VERSION 5.8 ;
BUSBITCHARS "[]" ;
DIVIDERCHAR "/" ;
UNITS
    DATABASE MICRONS 1000 ;
END UNITS

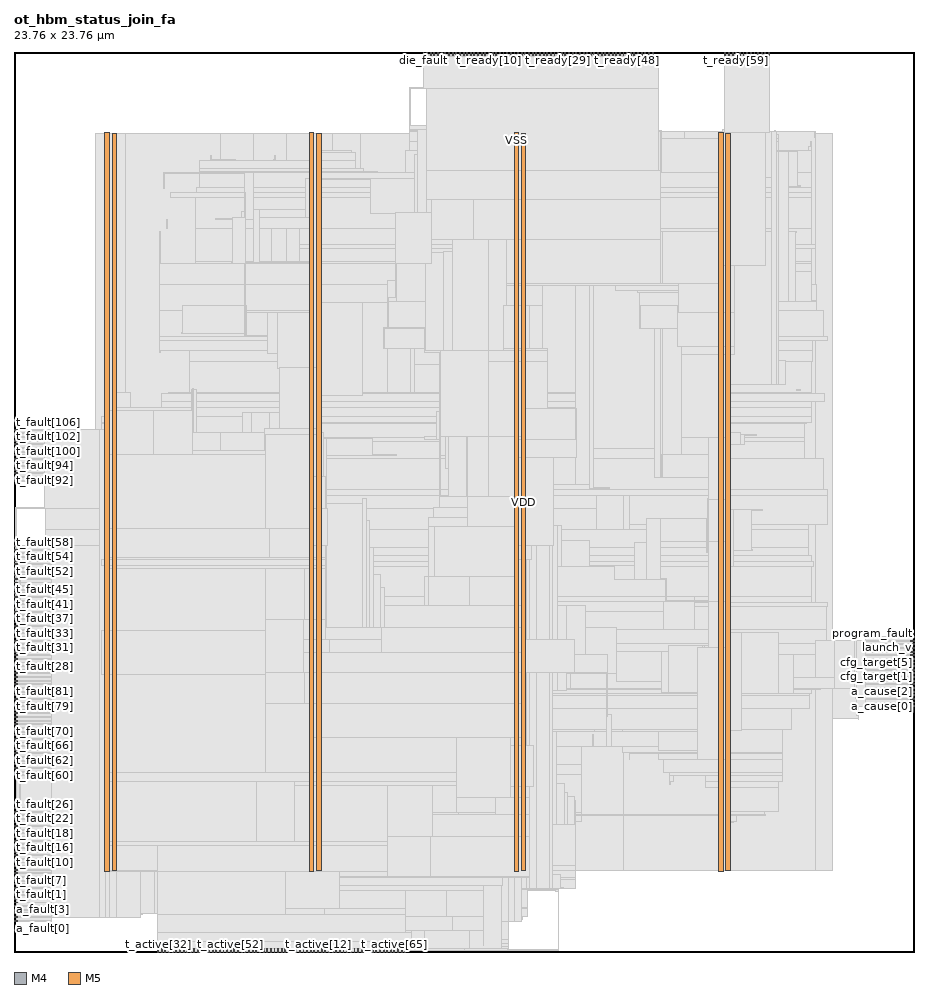
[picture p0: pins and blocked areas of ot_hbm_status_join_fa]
MACRO ot_hbm_status_join_fa
  FOREIGN ot_hbm_status_join_fa 0 0 ;
  CLASS BLOCK ;
  SIZE 23.76 BY 23.76 ;
  PIN a_cause[0]
    DIRECTION OUTPUT ;
    USE SIGNAL ;
    PORT
      LAYER M4 ;
        RECT  23.676 6.48 23.76 6.504 ;
    END
  END a_cause[0]
  PIN a_cause[1]
    DIRECTION OUTPUT ;
    USE SIGNAL ;
    PORT
      LAYER M4 ;
        RECT  23.676 6.576 23.76 6.6 ;
    END
  END a_cause[1]
  PIN a_cause[2]
    DIRECTION OUTPUT ;
    USE SIGNAL ;
    PORT
      LAYER M4 ;
        RECT  23.676 6.672 23.76 6.696 ;
    END
  END a_cause[2]
  PIN a_cause[3]
    DIRECTION OUTPUT ;
    USE SIGNAL ;
    PORT
      LAYER M4 ;
        RECT  23.676 6.768 23.76 6.792 ;
    END
  END a_cause[3]
  PIN a_fault[0]
    DIRECTION INPUT ;
    USE SIGNAL ;
    PORT
      LAYER M4 ;
        RECT  0 0.816 0.084 0.84 ;
    END
  END a_fault[0]
  PIN a_fault[1]
    DIRECTION INPUT ;
    USE SIGNAL ;
    PORT
      LAYER M4 ;
        RECT  0 0.912 0.084 0.936 ;
    END
  END a_fault[1]
  PIN a_fault[2]
    DIRECTION INPUT ;
    USE SIGNAL ;
    PORT
      LAYER M4 ;
        RECT  0 1.008 0.084 1.032 ;
    END
  END a_fault[2]
  PIN a_fault[3]
    DIRECTION INPUT ;
    USE SIGNAL ;
    PORT
      LAYER M4 ;
        RECT  0 1.104 0.084 1.128 ;
    END
  END a_fault[3]
  PIN block_ready
    DIRECTION OUTPUT ;
    USE SIGNAL ;
    PORT
      LAYER M4 ;
        RECT  23.676 6.864 23.76 6.888 ;
    END
  END block_ready
  PIN cfg_target[0]
    DIRECTION INPUT ;
    USE SIGNAL ;
    PORT
      LAYER M4 ;
        RECT  23.676 6.96 23.76 6.984 ;
    END
  END cfg_target[0]
  PIN cfg_target[1]
    DIRECTION INPUT ;
    USE SIGNAL ;
    PORT
      LAYER M4 ;
        RECT  23.676 7.056 23.76 7.08 ;
    END
  END cfg_target[1]
  PIN cfg_target[2]
    DIRECTION INPUT ;
    USE SIGNAL ;
    PORT
      LAYER M4 ;
        RECT  23.676 7.152 23.76 7.176 ;
    END
  END cfg_target[2]
  PIN cfg_target[3]
    DIRECTION INPUT ;
    USE SIGNAL ;
    PORT
      LAYER M4 ;
        RECT  23.676 7.248 23.76 7.272 ;
    END
  END cfg_target[3]
  PIN cfg_target[4]
    DIRECTION INPUT ;
    USE SIGNAL ;
    PORT
      LAYER M4 ;
        RECT  23.676 7.344 23.76 7.368 ;
    END
  END cfg_target[4]
  PIN cfg_target[5]
    DIRECTION INPUT ;
    USE SIGNAL ;
    PORT
      LAYER M4 ;
        RECT  23.676 7.44 23.76 7.464 ;
    END
  END cfg_target[5]
  PIN cfg_target[6]
    DIRECTION INPUT ;
    USE SIGNAL ;
    PORT
      LAYER M4 ;
        RECT  23.676 7.536 23.76 7.56 ;
    END
  END cfg_target[6]
  PIN cfg_target[7]
    DIRECTION INPUT ;
    USE SIGNAL ;
    PORT
      LAYER M4 ;
        RECT  23.676 7.632 23.76 7.656 ;
    END
  END cfg_target[7]
  PIN cfg_v
    DIRECTION INPUT ;
    USE SIGNAL ;
    PORT
      LAYER M4 ;
        RECT  23.676 7.728 23.76 7.752 ;
    END
  END cfg_v
  PIN clk
    DIRECTION INPUT ;
    USE SIGNAL ;
    PORT
      LAYER M4 ;
        RECT  23.676 7.824 23.76 7.848 ;
    END
  END clk
  PIN desc_v
    DIRECTION INPUT ;
    USE SIGNAL ;
    PORT
      LAYER M4 ;
        RECT  23.676 7.92 23.76 7.944 ;
    END
  END desc_v
  PIN die_fault
    DIRECTION OUTPUT ;
    USE SIGNAL ;
    PORT
      LAYER M5 ;
        RECT  10.8 23.676 10.824 23.76 ;
    END
  END die_fault
  PIN h_fault[0]
    DIRECTION INPUT ;
    USE SIGNAL ;
    PORT
      LAYER M5 ;
        RECT  10.896 23.676 10.92 23.76 ;
    END
  END h_fault[0]
  PIN h_fault[1]
    DIRECTION INPUT ;
    USE SIGNAL ;
    PORT
      LAYER M5 ;
        RECT  10.992 23.676 11.016 23.76 ;
    END
  END h_fault[1]
  PIN h_fault[2]
    DIRECTION INPUT ;
    USE SIGNAL ;
    PORT
      LAYER M5 ;
        RECT  11.088 23.676 11.112 23.76 ;
    END
  END h_fault[2]
  PIN h_fault[3]
    DIRECTION INPUT ;
    USE SIGNAL ;
    PORT
      LAYER M5 ;
        RECT  11.184 23.676 11.208 23.76 ;
    END
  END h_fault[3]
  PIN h_fault[4]
    DIRECTION INPUT ;
    USE SIGNAL ;
    PORT
      LAYER M5 ;
        RECT  11.28 23.676 11.304 23.76 ;
    END
  END h_fault[4]
  PIN h_fault[5]
    DIRECTION INPUT ;
    USE SIGNAL ;
    PORT
      LAYER M5 ;
        RECT  11.376 23.676 11.4 23.76 ;
    END
  END h_fault[5]
  PIN irq
    DIRECTION OUTPUT ;
    USE SIGNAL ;
    PORT
      LAYER M5 ;
        RECT  11.472 23.676 11.496 23.76 ;
    END
  END irq
  PIN launch_v
    DIRECTION INPUT ;
    USE SIGNAL ;
    PORT
      LAYER M4 ;
        RECT  23.676 8.016 23.76 8.04 ;
    END
  END launch_v
  PIN program_active
    DIRECTION OUTPUT ;
    USE SIGNAL ;
    PORT
      LAYER M4 ;
        RECT  23.676 8.112 23.76 8.136 ;
    END
  END program_active
  PIN program_fault
    DIRECTION OUTPUT ;
    USE SIGNAL ;
    PORT
      LAYER M4 ;
        RECT  23.676 8.208 23.76 8.232 ;
    END
  END program_fault
  PIN rst_n
    DIRECTION INPUT ;
    USE SIGNAL ;
    PORT
      LAYER M4 ;
        RECT  23.676 8.304 23.76 8.328 ;
    END
  END rst_n
  PIN t_active[0]
    DIRECTION INPUT ;
    USE SIGNAL ;
    PORT
      LAYER M5 ;
        RECT  6.864 0 6.888 0.084 ;
    END
  END t_active[0]
  PIN t_active[10]
    DIRECTION INPUT ;
    USE SIGNAL ;
    PORT
      LAYER M5 ;
        RECT  7.824 0 7.848 0.084 ;
    END
  END t_active[10]
  PIN t_active[11]
    DIRECTION INPUT ;
    USE SIGNAL ;
    PORT
      LAYER M5 ;
        RECT  7.92 0 7.944 0.084 ;
    END
  END t_active[11]
  PIN t_active[12]
    DIRECTION INPUT ;
    USE SIGNAL ;
    PORT
      LAYER M5 ;
        RECT  8.016 0 8.04 0.084 ;
    END
  END t_active[12]
  PIN t_active[13]
    DIRECTION INPUT ;
    USE SIGNAL ;
    PORT
      LAYER M5 ;
        RECT  8.112 0 8.136 0.084 ;
    END
  END t_active[13]
  PIN t_active[14]
    DIRECTION INPUT ;
    USE SIGNAL ;
    PORT
      LAYER M5 ;
        RECT  8.208 0 8.232 0.084 ;
    END
  END t_active[14]
  PIN t_active[15]
    DIRECTION INPUT ;
    USE SIGNAL ;
    PORT
      LAYER M5 ;
        RECT  8.304 0 8.328 0.084 ;
    END
  END t_active[15]
  PIN t_active[16]
    DIRECTION INPUT ;
    USE SIGNAL ;
    PORT
      LAYER M5 ;
        RECT  8.4 0 8.424 0.084 ;
    END
  END t_active[16]
  PIN t_active[17]
    DIRECTION INPUT ;
    USE SIGNAL ;
    PORT
      LAYER M5 ;
        RECT  8.496 0 8.52 0.084 ;
    END
  END t_active[17]
  PIN t_active[18]
    DIRECTION INPUT ;
    USE SIGNAL ;
    PORT
      LAYER M5 ;
        RECT  8.592 0 8.616 0.084 ;
    END
  END t_active[18]
  PIN t_active[19]
    DIRECTION INPUT ;
    USE SIGNAL ;
    PORT
      LAYER M5 ;
        RECT  8.688 0 8.712 0.084 ;
    END
  END t_active[19]
  PIN t_active[1]
    DIRECTION INPUT ;
    USE SIGNAL ;
    PORT
      LAYER M5 ;
        RECT  6.96 0 6.984 0.084 ;
    END
  END t_active[1]
  PIN t_active[20]
    DIRECTION INPUT ;
    USE SIGNAL ;
    PORT
      LAYER M5 ;
        RECT  8.784 0 8.808 0.084 ;
    END
  END t_active[20]
  PIN t_active[21]
    DIRECTION INPUT ;
    USE SIGNAL ;
    PORT
      LAYER M5 ;
        RECT  8.88 0 8.904 0.084 ;
    END
  END t_active[21]
  PIN t_active[22]
    DIRECTION INPUT ;
    USE SIGNAL ;
    PORT
      LAYER M5 ;
        RECT  8.976 0 9 0.084 ;
    END
  END t_active[22]
  PIN t_active[23]
    DIRECTION INPUT ;
    USE SIGNAL ;
    PORT
      LAYER M5 ;
        RECT  9.072 0 9.096 0.084 ;
    END
  END t_active[23]
  PIN t_active[24]
    DIRECTION INPUT ;
    USE SIGNAL ;
    PORT
      LAYER M5 ;
        RECT  9.168 0 9.192 0.084 ;
    END
  END t_active[24]
  PIN t_active[25]
    DIRECTION INPUT ;
    USE SIGNAL ;
    PORT
      LAYER M5 ;
        RECT  9.264 0 9.288 0.084 ;
    END
  END t_active[25]
  PIN t_active[26]
    DIRECTION INPUT ;
    USE SIGNAL ;
    PORT
      LAYER M5 ;
        RECT  9.36 0 9.384 0.084 ;
    END
  END t_active[26]
  PIN t_active[27]
    DIRECTION INPUT ;
    USE SIGNAL ;
    PORT
      LAYER M5 ;
        RECT  9.456 0 9.48 0.084 ;
    END
  END t_active[27]
  PIN t_active[28]
    DIRECTION INPUT ;
    USE SIGNAL ;
    PORT
      LAYER M5 ;
        RECT  9.552 0 9.576 0.084 ;
    END
  END t_active[28]
  PIN t_active[29]
    DIRECTION INPUT ;
    USE SIGNAL ;
    PORT
      LAYER M5 ;
        RECT  9.648 0 9.672 0.084 ;
    END
  END t_active[29]
  PIN t_active[2]
    DIRECTION INPUT ;
    USE SIGNAL ;
    PORT
      LAYER M5 ;
        RECT  7.056 0 7.08 0.084 ;
    END
  END t_active[2]
  PIN t_active[30]
    DIRECTION INPUT ;
    USE SIGNAL ;
    PORT
      LAYER M5 ;
        RECT  9.744 0 9.768 0.084 ;
    END
  END t_active[30]
  PIN t_active[31]
    DIRECTION INPUT ;
    USE SIGNAL ;
    PORT
      LAYER M5 ;
        RECT  9.84 0 9.864 0.084 ;
    END
  END t_active[31]
  PIN t_active[32]
    DIRECTION INPUT ;
    USE SIGNAL ;
    PORT
      LAYER M5 ;
        RECT  3.792 0 3.816 0.084 ;
    END
  END t_active[32]
  PIN t_active[33]
    DIRECTION INPUT ;
    USE SIGNAL ;
    PORT
      LAYER M5 ;
        RECT  3.888 0 3.912 0.084 ;
    END
  END t_active[33]
  PIN t_active[34]
    DIRECTION INPUT ;
    USE SIGNAL ;
    PORT
      LAYER M5 ;
        RECT  3.984 0 4.008 0.084 ;
    END
  END t_active[34]
  PIN t_active[35]
    DIRECTION INPUT ;
    USE SIGNAL ;
    PORT
      LAYER M5 ;
        RECT  4.08 0 4.104 0.084 ;
    END
  END t_active[35]
  PIN t_active[36]
    DIRECTION INPUT ;
    USE SIGNAL ;
    PORT
      LAYER M5 ;
        RECT  4.176 0 4.2 0.084 ;
    END
  END t_active[36]
  PIN t_active[37]
    DIRECTION INPUT ;
    USE SIGNAL ;
    PORT
      LAYER M5 ;
        RECT  4.272 0 4.296 0.084 ;
    END
  END t_active[37]
  PIN t_active[38]
    DIRECTION INPUT ;
    USE SIGNAL ;
    PORT
      LAYER M5 ;
        RECT  4.368 0 4.392 0.084 ;
    END
  END t_active[38]
  PIN t_active[39]
    DIRECTION INPUT ;
    USE SIGNAL ;
    PORT
      LAYER M5 ;
        RECT  4.464 0 4.488 0.084 ;
    END
  END t_active[39]
  PIN t_active[3]
    DIRECTION INPUT ;
    USE SIGNAL ;
    PORT
      LAYER M5 ;
        RECT  7.152 0 7.176 0.084 ;
    END
  END t_active[3]
  PIN t_active[40]
    DIRECTION INPUT ;
    USE SIGNAL ;
    PORT
      LAYER M5 ;
        RECT  4.56 0 4.584 0.084 ;
    END
  END t_active[40]
  PIN t_active[41]
    DIRECTION INPUT ;
    USE SIGNAL ;
    PORT
      LAYER M5 ;
        RECT  4.656 0 4.68 0.084 ;
    END
  END t_active[41]
  PIN t_active[42]
    DIRECTION INPUT ;
    USE SIGNAL ;
    PORT
      LAYER M5 ;
        RECT  4.752 0 4.776 0.084 ;
    END
  END t_active[42]
  PIN t_active[43]
    DIRECTION INPUT ;
    USE SIGNAL ;
    PORT
      LAYER M5 ;
        RECT  4.848 0 4.872 0.084 ;
    END
  END t_active[43]
  PIN t_active[44]
    DIRECTION INPUT ;
    USE SIGNAL ;
    PORT
      LAYER M5 ;
        RECT  4.944 0 4.968 0.084 ;
    END
  END t_active[44]
  PIN t_active[45]
    DIRECTION INPUT ;
    USE SIGNAL ;
    PORT
      LAYER M5 ;
        RECT  5.04 0 5.064 0.084 ;
    END
  END t_active[45]
  PIN t_active[46]
    DIRECTION INPUT ;
    USE SIGNAL ;
    PORT
      LAYER M5 ;
        RECT  5.136 0 5.16 0.084 ;
    END
  END t_active[46]
  PIN t_active[47]
    DIRECTION INPUT ;
    USE SIGNAL ;
    PORT
      LAYER M5 ;
        RECT  5.232 0 5.256 0.084 ;
    END
  END t_active[47]
  PIN t_active[48]
    DIRECTION INPUT ;
    USE SIGNAL ;
    PORT
      LAYER M5 ;
        RECT  5.328 0 5.352 0.084 ;
    END
  END t_active[48]
  PIN t_active[49]
    DIRECTION INPUT ;
    USE SIGNAL ;
    PORT
      LAYER M5 ;
        RECT  5.424 0 5.448 0.084 ;
    END
  END t_active[49]
  PIN t_active[4]
    DIRECTION INPUT ;
    USE SIGNAL ;
    PORT
      LAYER M5 ;
        RECT  7.248 0 7.272 0.084 ;
    END
  END t_active[4]
  PIN t_active[50]
    DIRECTION INPUT ;
    USE SIGNAL ;
    PORT
      LAYER M5 ;
        RECT  5.52 0 5.544 0.084 ;
    END
  END t_active[50]
  PIN t_active[51]
    DIRECTION INPUT ;
    USE SIGNAL ;
    PORT
      LAYER M5 ;
        RECT  5.616 0 5.64 0.084 ;
    END
  END t_active[51]
  PIN t_active[52]
    DIRECTION INPUT ;
    USE SIGNAL ;
    PORT
      LAYER M5 ;
        RECT  5.712 0 5.736 0.084 ;
    END
  END t_active[52]
  PIN t_active[53]
    DIRECTION INPUT ;
    USE SIGNAL ;
    PORT
      LAYER M5 ;
        RECT  5.808 0 5.832 0.084 ;
    END
  END t_active[53]
  PIN t_active[54]
    DIRECTION INPUT ;
    USE SIGNAL ;
    PORT
      LAYER M5 ;
        RECT  5.904 0 5.928 0.084 ;
    END
  END t_active[54]
  PIN t_active[55]
    DIRECTION INPUT ;
    USE SIGNAL ;
    PORT
      LAYER M5 ;
        RECT  6 0 6.024 0.084 ;
    END
  END t_active[55]
  PIN t_active[56]
    DIRECTION INPUT ;
    USE SIGNAL ;
    PORT
      LAYER M5 ;
        RECT  6.096 0 6.12 0.084 ;
    END
  END t_active[56]
  PIN t_active[57]
    DIRECTION INPUT ;
    USE SIGNAL ;
    PORT
      LAYER M5 ;
        RECT  6.192 0 6.216 0.084 ;
    END
  END t_active[57]
  PIN t_active[58]
    DIRECTION INPUT ;
    USE SIGNAL ;
    PORT
      LAYER M5 ;
        RECT  6.288 0 6.312 0.084 ;
    END
  END t_active[58]
  PIN t_active[59]
    DIRECTION INPUT ;
    USE SIGNAL ;
    PORT
      LAYER M5 ;
        RECT  6.384 0 6.408 0.084 ;
    END
  END t_active[59]
  PIN t_active[5]
    DIRECTION INPUT ;
    USE SIGNAL ;
    PORT
      LAYER M5 ;
        RECT  7.344 0 7.368 0.084 ;
    END
  END t_active[5]
  PIN t_active[60]
    DIRECTION INPUT ;
    USE SIGNAL ;
    PORT
      LAYER M5 ;
        RECT  6.48 0 6.504 0.084 ;
    END
  END t_active[60]
  PIN t_active[61]
    DIRECTION INPUT ;
    USE SIGNAL ;
    PORT
      LAYER M5 ;
        RECT  6.576 0 6.6 0.084 ;
    END
  END t_active[61]
  PIN t_active[62]
    DIRECTION INPUT ;
    USE SIGNAL ;
    PORT
      LAYER M5 ;
        RECT  6.672 0 6.696 0.084 ;
    END
  END t_active[62]
  PIN t_active[63]
    DIRECTION INPUT ;
    USE SIGNAL ;
    PORT
      LAYER M5 ;
        RECT  6.768 0 6.792 0.084 ;
    END
  END t_active[63]
  PIN t_active[64]
    DIRECTION INPUT ;
    USE SIGNAL ;
    PORT
      LAYER M5 ;
        RECT  9.936 0 9.96 0.084 ;
    END
  END t_active[64]
  PIN t_active[65]
    DIRECTION INPUT ;
    USE SIGNAL ;
    PORT
      LAYER M5 ;
        RECT  10.032 0 10.056 0.084 ;
    END
  END t_active[65]
  PIN t_active[66]
    DIRECTION INPUT ;
    USE SIGNAL ;
    PORT
      LAYER M5 ;
        RECT  10.128 0 10.152 0.084 ;
    END
  END t_active[66]
  PIN t_active[67]
    DIRECTION INPUT ;
    USE SIGNAL ;
    PORT
      LAYER M5 ;
        RECT  10.224 0 10.248 0.084 ;
    END
  END t_active[67]
  PIN t_active[68]
    DIRECTION INPUT ;
    USE SIGNAL ;
    PORT
      LAYER M5 ;
        RECT  10.32 0 10.344 0.084 ;
    END
  END t_active[68]
  PIN t_active[6]
    DIRECTION INPUT ;
    USE SIGNAL ;
    PORT
      LAYER M5 ;
        RECT  7.44 0 7.464 0.084 ;
    END
  END t_active[6]
  PIN t_active[7]
    DIRECTION INPUT ;
    USE SIGNAL ;
    PORT
      LAYER M5 ;
        RECT  7.536 0 7.56 0.084 ;
    END
  END t_active[7]
  PIN t_active[8]
    DIRECTION INPUT ;
    USE SIGNAL ;
    PORT
      LAYER M5 ;
        RECT  7.632 0 7.656 0.084 ;
    END
  END t_active[8]
  PIN t_active[9]
    DIRECTION INPUT ;
    USE SIGNAL ;
    PORT
      LAYER M5 ;
        RECT  7.728 0 7.752 0.084 ;
    END
  END t_active[9]
  PIN t_fault[0]
    DIRECTION INPUT ;
    USE SIGNAL ;
    PORT
      LAYER M4 ;
        RECT  0 1.2 0.084 1.224 ;
    END
  END t_fault[0]
  PIN t_fault[100]
    DIRECTION INPUT ;
    USE SIGNAL ;
    PORT
      LAYER M4 ;
        RECT  0 13.2 0.084 13.224 ;
    END
  END t_fault[100]
  PIN t_fault[101]
    DIRECTION INPUT ;
    USE SIGNAL ;
    PORT
      LAYER M4 ;
        RECT  0 13.296 0.084 13.32 ;
    END
  END t_fault[101]
  PIN t_fault[102]
    DIRECTION INPUT ;
    USE SIGNAL ;
    PORT
      LAYER M4 ;
        RECT  0 13.392 0.084 13.416 ;
    END
  END t_fault[102]
  PIN t_fault[103]
    DIRECTION INPUT ;
    USE SIGNAL ;
    PORT
      LAYER M4 ;
        RECT  0 13.488 0.084 13.512 ;
    END
  END t_fault[103]
  PIN t_fault[104]
    DIRECTION INPUT ;
    USE SIGNAL ;
    PORT
      LAYER M4 ;
        RECT  0 13.584 0.084 13.608 ;
    END
  END t_fault[104]
  PIN t_fault[105]
    DIRECTION INPUT ;
    USE SIGNAL ;
    PORT
      LAYER M4 ;
        RECT  0 13.68 0.084 13.704 ;
    END
  END t_fault[105]
  PIN t_fault[106]
    DIRECTION INPUT ;
    USE SIGNAL ;
    PORT
      LAYER M4 ;
        RECT  0 13.776 0.084 13.8 ;
    END
  END t_fault[106]
  PIN t_fault[10]
    DIRECTION INPUT ;
    USE SIGNAL ;
    PORT
      LAYER M4 ;
        RECT  0 2.16 0.084 2.184 ;
    END
  END t_fault[10]
  PIN t_fault[11]
    DIRECTION INPUT ;
    USE SIGNAL ;
    PORT
      LAYER M4 ;
        RECT  0 2.256 0.084 2.28 ;
    END
  END t_fault[11]
  PIN t_fault[12]
    DIRECTION INPUT ;
    USE SIGNAL ;
    PORT
      LAYER M4 ;
        RECT  0 2.352 0.084 2.376 ;
    END
  END t_fault[12]
  PIN t_fault[13]
    DIRECTION INPUT ;
    USE SIGNAL ;
    PORT
      LAYER M4 ;
        RECT  0 2.448 0.084 2.472 ;
    END
  END t_fault[13]
  PIN t_fault[14]
    DIRECTION INPUT ;
    USE SIGNAL ;
    PORT
      LAYER M4 ;
        RECT  0 2.544 0.084 2.568 ;
    END
  END t_fault[14]
  PIN t_fault[15]
    DIRECTION INPUT ;
    USE SIGNAL ;
    PORT
      LAYER M4 ;
        RECT  0 2.64 0.084 2.664 ;
    END
  END t_fault[15]
  PIN t_fault[16]
    DIRECTION INPUT ;
    USE SIGNAL ;
    PORT
      LAYER M4 ;
        RECT  0 2.736 0.084 2.76 ;
    END
  END t_fault[16]
  PIN t_fault[17]
    DIRECTION INPUT ;
    USE SIGNAL ;
    PORT
      LAYER M4 ;
        RECT  0 2.832 0.084 2.856 ;
    END
  END t_fault[17]
  PIN t_fault[18]
    DIRECTION INPUT ;
    USE SIGNAL ;
    PORT
      LAYER M4 ;
        RECT  0 2.928 0.084 2.952 ;
    END
  END t_fault[18]
  PIN t_fault[19]
    DIRECTION INPUT ;
    USE SIGNAL ;
    PORT
      LAYER M4 ;
        RECT  0 3.024 0.084 3.048 ;
    END
  END t_fault[19]
  PIN t_fault[1]
    DIRECTION INPUT ;
    USE SIGNAL ;
    PORT
      LAYER M4 ;
        RECT  0 1.296 0.084 1.32 ;
    END
  END t_fault[1]
  PIN t_fault[20]
    DIRECTION INPUT ;
    USE SIGNAL ;
    PORT
      LAYER M4 ;
        RECT  0 3.12 0.084 3.144 ;
    END
  END t_fault[20]
  PIN t_fault[21]
    DIRECTION INPUT ;
    USE SIGNAL ;
    PORT
      LAYER M4 ;
        RECT  0 3.216 0.084 3.24 ;
    END
  END t_fault[21]
  PIN t_fault[22]
    DIRECTION INPUT ;
    USE SIGNAL ;
    PORT
      LAYER M4 ;
        RECT  0 3.312 0.084 3.336 ;
    END
  END t_fault[22]
  PIN t_fault[23]
    DIRECTION INPUT ;
    USE SIGNAL ;
    PORT
      LAYER M4 ;
        RECT  0 3.408 0.084 3.432 ;
    END
  END t_fault[23]
  PIN t_fault[24]
    DIRECTION INPUT ;
    USE SIGNAL ;
    PORT
      LAYER M4 ;
        RECT  0 3.504 0.084 3.528 ;
    END
  END t_fault[24]
  PIN t_fault[25]
    DIRECTION INPUT ;
    USE SIGNAL ;
    PORT
      LAYER M4 ;
        RECT  0 3.6 0.084 3.624 ;
    END
  END t_fault[25]
  PIN t_fault[26]
    DIRECTION INPUT ;
    USE SIGNAL ;
    PORT
      LAYER M4 ;
        RECT  0 3.696 0.084 3.72 ;
    END
  END t_fault[26]
  PIN t_fault[27]
    DIRECTION INPUT ;
    USE SIGNAL ;
    PORT
      LAYER M4 ;
        RECT  0 3.792 0.084 3.816 ;
    END
  END t_fault[27]
  PIN t_fault[28]
    DIRECTION INPUT ;
    USE SIGNAL ;
    PORT
      LAYER M4 ;
        RECT  0 7.728 0.084 7.752 ;
    END
  END t_fault[28]
  PIN t_fault[29]
    DIRECTION INPUT ;
    USE SIGNAL ;
    PORT
      LAYER M4 ;
        RECT  0 7.824 0.084 7.848 ;
    END
  END t_fault[29]
  PIN t_fault[2]
    DIRECTION INPUT ;
    USE SIGNAL ;
    PORT
      LAYER M4 ;
        RECT  0 1.392 0.084 1.416 ;
    END
  END t_fault[2]
  PIN t_fault[30]
    DIRECTION INPUT ;
    USE SIGNAL ;
    PORT
      LAYER M4 ;
        RECT  0 7.92 0.084 7.944 ;
    END
  END t_fault[30]
  PIN t_fault[31]
    DIRECTION INPUT ;
    USE SIGNAL ;
    PORT
      LAYER M4 ;
        RECT  0 8.016 0.084 8.04 ;
    END
  END t_fault[31]
  PIN t_fault[32]
    DIRECTION INPUT ;
    USE SIGNAL ;
    PORT
      LAYER M4 ;
        RECT  0 8.112 0.084 8.136 ;
    END
  END t_fault[32]
  PIN t_fault[33]
    DIRECTION INPUT ;
    USE SIGNAL ;
    PORT
      LAYER M4 ;
        RECT  0 8.208 0.084 8.232 ;
    END
  END t_fault[33]
  PIN t_fault[34]
    DIRECTION INPUT ;
    USE SIGNAL ;
    PORT
      LAYER M4 ;
        RECT  0 8.304 0.084 8.328 ;
    END
  END t_fault[34]
  PIN t_fault[35]
    DIRECTION INPUT ;
    USE SIGNAL ;
    PORT
      LAYER M4 ;
        RECT  0 8.4 0.084 8.424 ;
    END
  END t_fault[35]
  PIN t_fault[36]
    DIRECTION INPUT ;
    USE SIGNAL ;
    PORT
      LAYER M4 ;
        RECT  0 8.496 0.084 8.52 ;
    END
  END t_fault[36]
  PIN t_fault[37]
    DIRECTION INPUT ;
    USE SIGNAL ;
    PORT
      LAYER M4 ;
        RECT  0 8.592 0.084 8.616 ;
    END
  END t_fault[37]
  PIN t_fault[38]
    DIRECTION INPUT ;
    USE SIGNAL ;
    PORT
      LAYER M4 ;
        RECT  0 8.688 0.084 8.712 ;
    END
  END t_fault[38]
  PIN t_fault[39]
    DIRECTION INPUT ;
    USE SIGNAL ;
    PORT
      LAYER M4 ;
        RECT  0 8.784 0.084 8.808 ;
    END
  END t_fault[39]
  PIN t_fault[3]
    DIRECTION INPUT ;
    USE SIGNAL ;
    PORT
      LAYER M4 ;
        RECT  0 1.488 0.084 1.512 ;
    END
  END t_fault[3]
  PIN t_fault[40]
    DIRECTION INPUT ;
    USE SIGNAL ;
    PORT
      LAYER M4 ;
        RECT  0 8.88 0.084 8.904 ;
    END
  END t_fault[40]
  PIN t_fault[41]
    DIRECTION INPUT ;
    USE SIGNAL ;
    PORT
      LAYER M4 ;
        RECT  0 8.976 0.084 9 ;
    END
  END t_fault[41]
  PIN t_fault[42]
    DIRECTION INPUT ;
    USE SIGNAL ;
    PORT
      LAYER M4 ;
        RECT  0 9.072 0.084 9.096 ;
    END
  END t_fault[42]
  PIN t_fault[43]
    DIRECTION INPUT ;
    USE SIGNAL ;
    PORT
      LAYER M4 ;
        RECT  0 9.168 0.084 9.192 ;
    END
  END t_fault[43]
  PIN t_fault[44]
    DIRECTION INPUT ;
    USE SIGNAL ;
    PORT
      LAYER M4 ;
        RECT  0 9.264 0.084 9.288 ;
    END
  END t_fault[44]
  PIN t_fault[45]
    DIRECTION INPUT ;
    USE SIGNAL ;
    PORT
      LAYER M4 ;
        RECT  0 9.36 0.084 9.384 ;
    END
  END t_fault[45]
  PIN t_fault[46]
    DIRECTION INPUT ;
    USE SIGNAL ;
    PORT
      LAYER M4 ;
        RECT  0 9.456 0.084 9.48 ;
    END
  END t_fault[46]
  PIN t_fault[47]
    DIRECTION INPUT ;
    USE SIGNAL ;
    PORT
      LAYER M4 ;
        RECT  0 9.552 0.084 9.576 ;
    END
  END t_fault[47]
  PIN t_fault[48]
    DIRECTION INPUT ;
    USE SIGNAL ;
    PORT
      LAYER M4 ;
        RECT  0 9.648 0.084 9.672 ;
    END
  END t_fault[48]
  PIN t_fault[49]
    DIRECTION INPUT ;
    USE SIGNAL ;
    PORT
      LAYER M4 ;
        RECT  0 9.744 0.084 9.768 ;
    END
  END t_fault[49]
  PIN t_fault[4]
    DIRECTION INPUT ;
    USE SIGNAL ;
    PORT
      LAYER M4 ;
        RECT  0 1.584 0.084 1.608 ;
    END
  END t_fault[4]
  PIN t_fault[50]
    DIRECTION INPUT ;
    USE SIGNAL ;
    PORT
      LAYER M4 ;
        RECT  0 9.84 0.084 9.864 ;
    END
  END t_fault[50]
  PIN t_fault[51]
    DIRECTION INPUT ;
    USE SIGNAL ;
    PORT
      LAYER M4 ;
        RECT  0 9.936 0.084 9.96 ;
    END
  END t_fault[51]
  PIN t_fault[52]
    DIRECTION INPUT ;
    USE SIGNAL ;
    PORT
      LAYER M4 ;
        RECT  0 10.032 0.084 10.056 ;
    END
  END t_fault[52]
  PIN t_fault[53]
    DIRECTION INPUT ;
    USE SIGNAL ;
    PORT
      LAYER M4 ;
        RECT  0 10.128 0.084 10.152 ;
    END
  END t_fault[53]
  PIN t_fault[54]
    DIRECTION INPUT ;
    USE SIGNAL ;
    PORT
      LAYER M4 ;
        RECT  0 10.224 0.084 10.248 ;
    END
  END t_fault[54]
  PIN t_fault[55]
    DIRECTION INPUT ;
    USE SIGNAL ;
    PORT
      LAYER M4 ;
        RECT  0 10.32 0.084 10.344 ;
    END
  END t_fault[55]
  PIN t_fault[56]
    DIRECTION INPUT ;
    USE SIGNAL ;
    PORT
      LAYER M4 ;
        RECT  0 10.416 0.084 10.44 ;
    END
  END t_fault[56]
  PIN t_fault[57]
    DIRECTION INPUT ;
    USE SIGNAL ;
    PORT
      LAYER M4 ;
        RECT  0 10.512 0.084 10.536 ;
    END
  END t_fault[57]
  PIN t_fault[58]
    DIRECTION INPUT ;
    USE SIGNAL ;
    PORT
      LAYER M4 ;
        RECT  0 10.608 0.084 10.632 ;
    END
  END t_fault[58]
  PIN t_fault[59]
    DIRECTION INPUT ;
    USE SIGNAL ;
    PORT
      LAYER M4 ;
        RECT  0 10.704 0.084 10.728 ;
    END
  END t_fault[59]
  PIN t_fault[5]
    DIRECTION INPUT ;
    USE SIGNAL ;
    PORT
      LAYER M4 ;
        RECT  0 1.68 0.084 1.704 ;
    END
  END t_fault[5]
  PIN t_fault[60]
    DIRECTION INPUT ;
    USE SIGNAL ;
    PORT
      LAYER M4 ;
        RECT  0 4.656 0.084 4.68 ;
    END
  END t_fault[60]
  PIN t_fault[61]
    DIRECTION INPUT ;
    USE SIGNAL ;
    PORT
      LAYER M4 ;
        RECT  0 4.752 0.084 4.776 ;
    END
  END t_fault[61]
  PIN t_fault[62]
    DIRECTION INPUT ;
    USE SIGNAL ;
    PORT
      LAYER M4 ;
        RECT  0 4.848 0.084 4.872 ;
    END
  END t_fault[62]
  PIN t_fault[63]
    DIRECTION INPUT ;
    USE SIGNAL ;
    PORT
      LAYER M4 ;
        RECT  0 4.944 0.084 4.968 ;
    END
  END t_fault[63]
  PIN t_fault[64]
    DIRECTION INPUT ;
    USE SIGNAL ;
    PORT
      LAYER M4 ;
        RECT  0 5.04 0.084 5.064 ;
    END
  END t_fault[64]
  PIN t_fault[65]
    DIRECTION INPUT ;
    USE SIGNAL ;
    PORT
      LAYER M4 ;
        RECT  0 5.136 0.084 5.16 ;
    END
  END t_fault[65]
  PIN t_fault[66]
    DIRECTION INPUT ;
    USE SIGNAL ;
    PORT
      LAYER M4 ;
        RECT  0 5.232 0.084 5.256 ;
    END
  END t_fault[66]
  PIN t_fault[67]
    DIRECTION INPUT ;
    USE SIGNAL ;
    PORT
      LAYER M4 ;
        RECT  0 5.328 0.084 5.352 ;
    END
  END t_fault[67]
  PIN t_fault[68]
    DIRECTION INPUT ;
    USE SIGNAL ;
    PORT
      LAYER M4 ;
        RECT  0 5.424 0.084 5.448 ;
    END
  END t_fault[68]
  PIN t_fault[69]
    DIRECTION INPUT ;
    USE SIGNAL ;
    PORT
      LAYER M4 ;
        RECT  0 5.52 0.084 5.544 ;
    END
  END t_fault[69]
  PIN t_fault[6]
    DIRECTION INPUT ;
    USE SIGNAL ;
    PORT
      LAYER M4 ;
        RECT  0 1.776 0.084 1.8 ;
    END
  END t_fault[6]
  PIN t_fault[70]
    DIRECTION INPUT ;
    USE SIGNAL ;
    PORT
      LAYER M4 ;
        RECT  0 5.616 0.084 5.64 ;
    END
  END t_fault[70]
  PIN t_fault[71]
    DIRECTION INPUT ;
    USE SIGNAL ;
    PORT
      LAYER M4 ;
        RECT  0 5.712 0.084 5.736 ;
    END
  END t_fault[71]
  PIN t_fault[72]
    DIRECTION INPUT ;
    USE SIGNAL ;
    PORT
      LAYER M4 ;
        RECT  0 5.808 0.084 5.832 ;
    END
  END t_fault[72]
  PIN t_fault[73]
    DIRECTION INPUT ;
    USE SIGNAL ;
    PORT
      LAYER M4 ;
        RECT  0 5.904 0.084 5.928 ;
    END
  END t_fault[73]
  PIN t_fault[74]
    DIRECTION INPUT ;
    USE SIGNAL ;
    PORT
      LAYER M4 ;
        RECT  0 6 0.084 6.024 ;
    END
  END t_fault[74]
  PIN t_fault[75]
    DIRECTION INPUT ;
    USE SIGNAL ;
    PORT
      LAYER M4 ;
        RECT  0 6.096 0.084 6.12 ;
    END
  END t_fault[75]
  PIN t_fault[76]
    DIRECTION INPUT ;
    USE SIGNAL ;
    PORT
      LAYER M4 ;
        RECT  0 6.192 0.084 6.216 ;
    END
  END t_fault[76]
  PIN t_fault[77]
    DIRECTION INPUT ;
    USE SIGNAL ;
    PORT
      LAYER M4 ;
        RECT  0 6.288 0.084 6.312 ;
    END
  END t_fault[77]
  PIN t_fault[78]
    DIRECTION INPUT ;
    USE SIGNAL ;
    PORT
      LAYER M4 ;
        RECT  0 6.384 0.084 6.408 ;
    END
  END t_fault[78]
  PIN t_fault[79]
    DIRECTION INPUT ;
    USE SIGNAL ;
    PORT
      LAYER M4 ;
        RECT  0 6.48 0.084 6.504 ;
    END
  END t_fault[79]
  PIN t_fault[7]
    DIRECTION INPUT ;
    USE SIGNAL ;
    PORT
      LAYER M4 ;
        RECT  0 1.872 0.084 1.896 ;
    END
  END t_fault[7]
  PIN t_fault[80]
    DIRECTION INPUT ;
    USE SIGNAL ;
    PORT
      LAYER M4 ;
        RECT  0 6.576 0.084 6.6 ;
    END
  END t_fault[80]
  PIN t_fault[81]
    DIRECTION INPUT ;
    USE SIGNAL ;
    PORT
      LAYER M4 ;
        RECT  0 6.672 0.084 6.696 ;
    END
  END t_fault[81]
  PIN t_fault[82]
    DIRECTION INPUT ;
    USE SIGNAL ;
    PORT
      LAYER M4 ;
        RECT  0 6.768 0.084 6.792 ;
    END
  END t_fault[82]
  PIN t_fault[83]
    DIRECTION INPUT ;
    USE SIGNAL ;
    PORT
      LAYER M4 ;
        RECT  0 6.864 0.084 6.888 ;
    END
  END t_fault[83]
  PIN t_fault[84]
    DIRECTION INPUT ;
    USE SIGNAL ;
    PORT
      LAYER M4 ;
        RECT  0 6.96 0.084 6.984 ;
    END
  END t_fault[84]
  PIN t_fault[85]
    DIRECTION INPUT ;
    USE SIGNAL ;
    PORT
      LAYER M4 ;
        RECT  0 7.056 0.084 7.08 ;
    END
  END t_fault[85]
  PIN t_fault[86]
    DIRECTION INPUT ;
    USE SIGNAL ;
    PORT
      LAYER M4 ;
        RECT  0 7.152 0.084 7.176 ;
    END
  END t_fault[86]
  PIN t_fault[87]
    DIRECTION INPUT ;
    USE SIGNAL ;
    PORT
      LAYER M4 ;
        RECT  0 7.248 0.084 7.272 ;
    END
  END t_fault[87]
  PIN t_fault[88]
    DIRECTION INPUT ;
    USE SIGNAL ;
    PORT
      LAYER M4 ;
        RECT  0 7.344 0.084 7.368 ;
    END
  END t_fault[88]
  PIN t_fault[89]
    DIRECTION INPUT ;
    USE SIGNAL ;
    PORT
      LAYER M4 ;
        RECT  0 7.44 0.084 7.464 ;
    END
  END t_fault[89]
  PIN t_fault[8]
    DIRECTION INPUT ;
    USE SIGNAL ;
    PORT
      LAYER M4 ;
        RECT  0 1.968 0.084 1.992 ;
    END
  END t_fault[8]
  PIN t_fault[90]
    DIRECTION INPUT ;
    USE SIGNAL ;
    PORT
      LAYER M4 ;
        RECT  0 7.536 0.084 7.56 ;
    END
  END t_fault[90]
  PIN t_fault[91]
    DIRECTION INPUT ;
    USE SIGNAL ;
    PORT
      LAYER M4 ;
        RECT  0 7.632 0.084 7.656 ;
    END
  END t_fault[91]
  PIN t_fault[92]
    DIRECTION INPUT ;
    USE SIGNAL ;
    PORT
      LAYER M4 ;
        RECT  0 12.432 0.084 12.456 ;
    END
  END t_fault[92]
  PIN t_fault[93]
    DIRECTION INPUT ;
    USE SIGNAL ;
    PORT
      LAYER M4 ;
        RECT  0 12.528 0.084 12.552 ;
    END
  END t_fault[93]
  PIN t_fault[94]
    DIRECTION INPUT ;
    USE SIGNAL ;
    PORT
      LAYER M4 ;
        RECT  0 12.624 0.084 12.648 ;
    END
  END t_fault[94]
  PIN t_fault[95]
    DIRECTION INPUT ;
    USE SIGNAL ;
    PORT
      LAYER M4 ;
        RECT  0 12.72 0.084 12.744 ;
    END
  END t_fault[95]
  PIN t_fault[96]
    DIRECTION INPUT ;
    USE SIGNAL ;
    PORT
      LAYER M4 ;
        RECT  0 12.816 0.084 12.84 ;
    END
  END t_fault[96]
  PIN t_fault[97]
    DIRECTION INPUT ;
    USE SIGNAL ;
    PORT
      LAYER M4 ;
        RECT  0 12.912 0.084 12.936 ;
    END
  END t_fault[97]
  PIN t_fault[98]
    DIRECTION INPUT ;
    USE SIGNAL ;
    PORT
      LAYER M4 ;
        RECT  0 13.008 0.084 13.032 ;
    END
  END t_fault[98]
  PIN t_fault[99]
    DIRECTION INPUT ;
    USE SIGNAL ;
    PORT
      LAYER M4 ;
        RECT  0 13.104 0.084 13.128 ;
    END
  END t_fault[99]
  PIN t_fault[9]
    DIRECTION INPUT ;
    USE SIGNAL ;
    PORT
      LAYER M4 ;
        RECT  0 2.064 0.084 2.088 ;
    END
  END t_fault[9]
  PIN t_ready[0]
    DIRECTION INPUT ;
    USE SIGNAL ;
    PORT
      LAYER M5 ;
        RECT  11.568 23.676 11.592 23.76 ;
    END
  END t_ready[0]
  PIN t_ready[10]
    DIRECTION INPUT ;
    USE SIGNAL ;
    PORT
      LAYER M5 ;
        RECT  12.528 23.676 12.552 23.76 ;
    END
  END t_ready[10]
  PIN t_ready[11]
    DIRECTION INPUT ;
    USE SIGNAL ;
    PORT
      LAYER M5 ;
        RECT  12.624 23.676 12.648 23.76 ;
    END
  END t_ready[11]
  PIN t_ready[12]
    DIRECTION INPUT ;
    USE SIGNAL ;
    PORT
      LAYER M5 ;
        RECT  12.72 23.676 12.744 23.76 ;
    END
  END t_ready[12]
  PIN t_ready[13]
    DIRECTION INPUT ;
    USE SIGNAL ;
    PORT
      LAYER M5 ;
        RECT  12.816 23.676 12.84 23.76 ;
    END
  END t_ready[13]
  PIN t_ready[14]
    DIRECTION INPUT ;
    USE SIGNAL ;
    PORT
      LAYER M5 ;
        RECT  12.912 23.676 12.936 23.76 ;
    END
  END t_ready[14]
  PIN t_ready[15]
    DIRECTION INPUT ;
    USE SIGNAL ;
    PORT
      LAYER M5 ;
        RECT  13.008 23.676 13.032 23.76 ;
    END
  END t_ready[15]
  PIN t_ready[16]
    DIRECTION INPUT ;
    USE SIGNAL ;
    PORT
      LAYER M5 ;
        RECT  13.104 23.676 13.128 23.76 ;
    END
  END t_ready[16]
  PIN t_ready[17]
    DIRECTION INPUT ;
    USE SIGNAL ;
    PORT
      LAYER M5 ;
        RECT  13.2 23.676 13.224 23.76 ;
    END
  END t_ready[17]
  PIN t_ready[18]
    DIRECTION INPUT ;
    USE SIGNAL ;
    PORT
      LAYER M5 ;
        RECT  13.296 23.676 13.32 23.76 ;
    END
  END t_ready[18]
  PIN t_ready[19]
    DIRECTION INPUT ;
    USE SIGNAL ;
    PORT
      LAYER M5 ;
        RECT  13.392 23.676 13.416 23.76 ;
    END
  END t_ready[19]
  PIN t_ready[1]
    DIRECTION INPUT ;
    USE SIGNAL ;
    PORT
      LAYER M5 ;
        RECT  11.664 23.676 11.688 23.76 ;
    END
  END t_ready[1]
  PIN t_ready[20]
    DIRECTION INPUT ;
    USE SIGNAL ;
    PORT
      LAYER M5 ;
        RECT  13.488 23.676 13.512 23.76 ;
    END
  END t_ready[20]
  PIN t_ready[21]
    DIRECTION INPUT ;
    USE SIGNAL ;
    PORT
      LAYER M5 ;
        RECT  13.584 23.676 13.608 23.76 ;
    END
  END t_ready[21]
  PIN t_ready[22]
    DIRECTION INPUT ;
    USE SIGNAL ;
    PORT
      LAYER M5 ;
        RECT  13.68 23.676 13.704 23.76 ;
    END
  END t_ready[22]
  PIN t_ready[23]
    DIRECTION INPUT ;
    USE SIGNAL ;
    PORT
      LAYER M5 ;
        RECT  13.776 23.676 13.8 23.76 ;
    END
  END t_ready[23]
  PIN t_ready[24]
    DIRECTION INPUT ;
    USE SIGNAL ;
    PORT
      LAYER M5 ;
        RECT  13.872 23.676 13.896 23.76 ;
    END
  END t_ready[24]
  PIN t_ready[25]
    DIRECTION INPUT ;
    USE SIGNAL ;
    PORT
      LAYER M5 ;
        RECT  13.968 23.676 13.992 23.76 ;
    END
  END t_ready[25]
  PIN t_ready[26]
    DIRECTION INPUT ;
    USE SIGNAL ;
    PORT
      LAYER M5 ;
        RECT  14.064 23.676 14.088 23.76 ;
    END
  END t_ready[26]
  PIN t_ready[27]
    DIRECTION INPUT ;
    USE SIGNAL ;
    PORT
      LAYER M5 ;
        RECT  14.16 23.676 14.184 23.76 ;
    END
  END t_ready[27]
  PIN t_ready[28]
    DIRECTION INPUT ;
    USE SIGNAL ;
    PORT
      LAYER M5 ;
        RECT  14.256 23.676 14.28 23.76 ;
    END
  END t_ready[28]
  PIN t_ready[29]
    DIRECTION INPUT ;
    USE SIGNAL ;
    PORT
      LAYER M5 ;
        RECT  14.352 23.676 14.376 23.76 ;
    END
  END t_ready[29]
  PIN t_ready[2]
    DIRECTION INPUT ;
    USE SIGNAL ;
    PORT
      LAYER M5 ;
        RECT  11.76 23.676 11.784 23.76 ;
    END
  END t_ready[2]
  PIN t_ready[30]
    DIRECTION INPUT ;
    USE SIGNAL ;
    PORT
      LAYER M5 ;
        RECT  14.448 23.676 14.472 23.76 ;
    END
  END t_ready[30]
  PIN t_ready[31]
    DIRECTION INPUT ;
    USE SIGNAL ;
    PORT
      LAYER M5 ;
        RECT  14.544 23.676 14.568 23.76 ;
    END
  END t_ready[31]
  PIN t_ready[32]
    DIRECTION INPUT ;
    USE SIGNAL ;
    PORT
      LAYER M5 ;
        RECT  14.64 23.676 14.664 23.76 ;
    END
  END t_ready[32]
  PIN t_ready[33]
    DIRECTION INPUT ;
    USE SIGNAL ;
    PORT
      LAYER M5 ;
        RECT  14.736 23.676 14.76 23.76 ;
    END
  END t_ready[33]
  PIN t_ready[34]
    DIRECTION INPUT ;
    USE SIGNAL ;
    PORT
      LAYER M5 ;
        RECT  14.832 23.676 14.856 23.76 ;
    END
  END t_ready[34]
  PIN t_ready[35]
    DIRECTION INPUT ;
    USE SIGNAL ;
    PORT
      LAYER M5 ;
        RECT  14.928 23.676 14.952 23.76 ;
    END
  END t_ready[35]
  PIN t_ready[36]
    DIRECTION INPUT ;
    USE SIGNAL ;
    PORT
      LAYER M5 ;
        RECT  15.024 23.676 15.048 23.76 ;
    END
  END t_ready[36]
  PIN t_ready[37]
    DIRECTION INPUT ;
    USE SIGNAL ;
    PORT
      LAYER M5 ;
        RECT  15.12 23.676 15.144 23.76 ;
    END
  END t_ready[37]
  PIN t_ready[38]
    DIRECTION INPUT ;
    USE SIGNAL ;
    PORT
      LAYER M5 ;
        RECT  15.216 23.676 15.24 23.76 ;
    END
  END t_ready[38]
  PIN t_ready[39]
    DIRECTION INPUT ;
    USE SIGNAL ;
    PORT
      LAYER M5 ;
        RECT  15.312 23.676 15.336 23.76 ;
    END
  END t_ready[39]
  PIN t_ready[3]
    DIRECTION INPUT ;
    USE SIGNAL ;
    PORT
      LAYER M5 ;
        RECT  11.856 23.676 11.88 23.76 ;
    END
  END t_ready[3]
  PIN t_ready[40]
    DIRECTION INPUT ;
    USE SIGNAL ;
    PORT
      LAYER M5 ;
        RECT  15.408 23.676 15.432 23.76 ;
    END
  END t_ready[40]
  PIN t_ready[41]
    DIRECTION INPUT ;
    USE SIGNAL ;
    PORT
      LAYER M5 ;
        RECT  15.504 23.676 15.528 23.76 ;
    END
  END t_ready[41]
  PIN t_ready[42]
    DIRECTION INPUT ;
    USE SIGNAL ;
    PORT
      LAYER M5 ;
        RECT  15.6 23.676 15.624 23.76 ;
    END
  END t_ready[42]
  PIN t_ready[43]
    DIRECTION INPUT ;
    USE SIGNAL ;
    PORT
      LAYER M5 ;
        RECT  15.696 23.676 15.72 23.76 ;
    END
  END t_ready[43]
  PIN t_ready[44]
    DIRECTION INPUT ;
    USE SIGNAL ;
    PORT
      LAYER M5 ;
        RECT  15.792 23.676 15.816 23.76 ;
    END
  END t_ready[44]
  PIN t_ready[45]
    DIRECTION INPUT ;
    USE SIGNAL ;
    PORT
      LAYER M5 ;
        RECT  15.888 23.676 15.912 23.76 ;
    END
  END t_ready[45]
  PIN t_ready[46]
    DIRECTION INPUT ;
    USE SIGNAL ;
    PORT
      LAYER M5 ;
        RECT  15.984 23.676 16.008 23.76 ;
    END
  END t_ready[46]
  PIN t_ready[47]
    DIRECTION INPUT ;
    USE SIGNAL ;
    PORT
      LAYER M5 ;
        RECT  16.08 23.676 16.104 23.76 ;
    END
  END t_ready[47]
  PIN t_ready[48]
    DIRECTION INPUT ;
    USE SIGNAL ;
    PORT
      LAYER M5 ;
        RECT  16.176 23.676 16.2 23.76 ;
    END
  END t_ready[48]
  PIN t_ready[49]
    DIRECTION INPUT ;
    USE SIGNAL ;
    PORT
      LAYER M5 ;
        RECT  16.272 23.676 16.296 23.76 ;
    END
  END t_ready[49]
  PIN t_ready[4]
    DIRECTION INPUT ;
    USE SIGNAL ;
    PORT
      LAYER M5 ;
        RECT  11.952 23.676 11.976 23.76 ;
    END
  END t_ready[4]
  PIN t_ready[50]
    DIRECTION INPUT ;
    USE SIGNAL ;
    PORT
      LAYER M5 ;
        RECT  16.368 23.676 16.392 23.76 ;
    END
  END t_ready[50]
  PIN t_ready[51]
    DIRECTION INPUT ;
    USE SIGNAL ;
    PORT
      LAYER M5 ;
        RECT  16.464 23.676 16.488 23.76 ;
    END
  END t_ready[51]
  PIN t_ready[52]
    DIRECTION INPUT ;
    USE SIGNAL ;
    PORT
      LAYER M5 ;
        RECT  16.56 23.676 16.584 23.76 ;
    END
  END t_ready[52]
  PIN t_ready[53]
    DIRECTION INPUT ;
    USE SIGNAL ;
    PORT
      LAYER M5 ;
        RECT  16.656 23.676 16.68 23.76 ;
    END
  END t_ready[53]
  PIN t_ready[54]
    DIRECTION INPUT ;
    USE SIGNAL ;
    PORT
      LAYER M5 ;
        RECT  16.752 23.676 16.776 23.76 ;
    END
  END t_ready[54]
  PIN t_ready[55]
    DIRECTION INPUT ;
    USE SIGNAL ;
    PORT
      LAYER M5 ;
        RECT  16.848 23.676 16.872 23.76 ;
    END
  END t_ready[55]
  PIN t_ready[56]
    DIRECTION INPUT ;
    USE SIGNAL ;
    PORT
      LAYER M5 ;
        RECT  18.768 23.676 18.792 23.76 ;
    END
  END t_ready[56]
  PIN t_ready[57]
    DIRECTION INPUT ;
    USE SIGNAL ;
    PORT
      LAYER M5 ;
        RECT  18.864 23.676 18.888 23.76 ;
    END
  END t_ready[57]
  PIN t_ready[58]
    DIRECTION INPUT ;
    USE SIGNAL ;
    PORT
      LAYER M5 ;
        RECT  18.96 23.676 18.984 23.76 ;
    END
  END t_ready[58]
  PIN t_ready[59]
    DIRECTION INPUT ;
    USE SIGNAL ;
    PORT
      LAYER M5 ;
        RECT  19.056 23.676 19.08 23.76 ;
    END
  END t_ready[59]
  PIN t_ready[5]
    DIRECTION INPUT ;
    USE SIGNAL ;
    PORT
      LAYER M5 ;
        RECT  12.048 23.676 12.072 23.76 ;
    END
  END t_ready[5]
  PIN t_ready[60]
    DIRECTION INPUT ;
    USE SIGNAL ;
    PORT
      LAYER M5 ;
        RECT  19.152 23.676 19.176 23.76 ;
    END
  END t_ready[60]
  PIN t_ready[61]
    DIRECTION INPUT ;
    USE SIGNAL ;
    PORT
      LAYER M5 ;
        RECT  19.248 23.676 19.272 23.76 ;
    END
  END t_ready[61]
  PIN t_ready[62]
    DIRECTION INPUT ;
    USE SIGNAL ;
    PORT
      LAYER M5 ;
        RECT  19.344 23.676 19.368 23.76 ;
    END
  END t_ready[62]
  PIN t_ready[63]
    DIRECTION INPUT ;
    USE SIGNAL ;
    PORT
      LAYER M5 ;
        RECT  19.44 23.676 19.464 23.76 ;
    END
  END t_ready[63]
  PIN t_ready[64]
    DIRECTION INPUT ;
    USE SIGNAL ;
    PORT
      LAYER M5 ;
        RECT  19.536 23.676 19.56 23.76 ;
    END
  END t_ready[64]
  PIN t_ready[65]
    DIRECTION INPUT ;
    USE SIGNAL ;
    PORT
      LAYER M5 ;
        RECT  19.632 23.676 19.656 23.76 ;
    END
  END t_ready[65]
  PIN t_ready[66]
    DIRECTION INPUT ;
    USE SIGNAL ;
    PORT
      LAYER M5 ;
        RECT  19.728 23.676 19.752 23.76 ;
    END
  END t_ready[66]
  PIN t_ready[67]
    DIRECTION INPUT ;
    USE SIGNAL ;
    PORT
      LAYER M5 ;
        RECT  19.824 23.676 19.848 23.76 ;
    END
  END t_ready[67]
  PIN t_ready[68]
    DIRECTION INPUT ;
    USE SIGNAL ;
    PORT
      LAYER M5 ;
        RECT  19.92 23.676 19.944 23.76 ;
    END
  END t_ready[68]
  PIN t_ready[6]
    DIRECTION INPUT ;
    USE SIGNAL ;
    PORT
      LAYER M5 ;
        RECT  12.144 23.676 12.168 23.76 ;
    END
  END t_ready[6]
  PIN t_ready[7]
    DIRECTION INPUT ;
    USE SIGNAL ;
    PORT
      LAYER M5 ;
        RECT  12.24 23.676 12.264 23.76 ;
    END
  END t_ready[7]
  PIN t_ready[8]
    DIRECTION INPUT ;
    USE SIGNAL ;
    PORT
      LAYER M5 ;
        RECT  12.336 23.676 12.36 23.76 ;
    END
  END t_ready[8]
  PIN t_ready[9]
    DIRECTION INPUT ;
    USE SIGNAL ;
    PORT
      LAYER M5 ;
        RECT  12.432 23.676 12.456 23.76 ;
    END
  END t_ready[9]
  PIN VDD
    DIRECTION INOUT ;
    USE POWER ;
    PORT
      LAYER M5 ;
        RECT  18.792 2.151 18.912 21.609 ;
        RECT  13.392 2.151 13.512 21.609 ;
        RECT  7.992 2.151 8.112 21.609 ;
        RECT  2.592 2.151 2.712 21.609 ;
    END
  END VDD
  PIN VSS
    DIRECTION INOUT ;
    USE GROUND ;
    PORT
      LAYER M5 ;
        RECT  18.6 2.137 18.72 21.623 ;
        RECT  13.2 2.137 13.32 21.623 ;
        RECT  7.8 2.137 7.92 21.623 ;
        RECT  2.4 2.137 2.52 21.623 ;
    END
  END VSS
  # OT_OBS_CLOSED layer=M5 d_um=1.536 added=40
  OBS
    LAYER RVTN ;
     RECT  2.16 2.16 21.6 2.295 ;
     RECT  2.16 2.565 21.6 2.835 ;
     RECT  2.16 3.105 21.6 3.375 ;
     RECT  2.16 3.645 21.6 3.915 ;
     RECT  2.16 4.185 21.6 4.455 ;
     RECT  2.16 4.725 21.6 4.995 ;
     RECT  2.16 5.265 21.6 5.535 ;
     RECT  2.16 5.805 21.6 6.075 ;
     RECT  2.16 6.345 21.6 6.615 ;
     RECT  2.16 6.885 21.6 7.155 ;
     RECT  2.16 7.425 21.6 7.695 ;
     RECT  2.16 7.965 21.6 8.235 ;
     RECT  2.16 8.505 21.6 8.775 ;
     RECT  2.16 9.045 21.6 9.315 ;
     RECT  2.16 9.585 21.6 9.855 ;
     RECT  2.16 10.125 21.6 10.395 ;
     RECT  2.16 10.665 21.6 10.935 ;
     RECT  2.16 11.205 21.6 11.475 ;
     RECT  2.16 11.745 21.6 12.015 ;
     RECT  2.16 12.285 21.6 12.555 ;
     RECT  2.16 12.825 21.6 13.095 ;
     RECT  2.16 13.365 21.6 13.635 ;
     RECT  2.16 13.905 21.6 14.175 ;
     RECT  2.16 14.445 21.6 14.715 ;
     RECT  2.16 14.985 21.6 15.255 ;
     RECT  2.16 15.525 21.6 15.795 ;
     RECT  2.16 16.065 21.6 16.335 ;
     RECT  2.16 16.605 21.6 16.875 ;
     RECT  2.16 17.145 21.6 17.415 ;
     RECT  2.16 17.685 21.6 17.955 ;
     RECT  2.16 18.225 21.6 18.495 ;
     RECT  2.16 18.765 21.6 19.035 ;
     RECT  2.16 19.305 21.6 19.575 ;
     RECT  2.16 19.845 21.6 20.115 ;
     RECT  2.16 20.385 21.6 20.655 ;
     RECT  2.16 20.925 21.6 21.195 ;
     RECT  2.16 21.465 21.6 21.6 ;
    LAYER RVTP ;
     RECT  2.16 2.295 21.6 2.565 ;
     RECT  2.16 2.835 21.6 3.105 ;
     RECT  2.16 3.375 21.6 3.645 ;
     RECT  2.16 3.915 21.6 4.185 ;
     RECT  2.16 4.455 21.6 4.725 ;
     RECT  2.16 4.995 21.6 5.265 ;
     RECT  2.16 5.535 21.6 5.805 ;
     RECT  2.16 6.075 21.6 6.345 ;
     RECT  2.16 6.615 21.6 6.885 ;
     RECT  2.16 7.155 21.6 7.425 ;
     RECT  2.16 7.695 21.6 7.965 ;
     RECT  2.16 8.235 21.6 8.505 ;
     RECT  2.16 8.775 21.6 9.045 ;
     RECT  2.16 9.315 21.6 9.585 ;
     RECT  2.16 9.855 21.6 10.125 ;
     RECT  2.16 10.395 21.6 10.665 ;
     RECT  2.16 10.935 21.6 11.205 ;
     RECT  2.16 11.475 21.6 11.745 ;
     RECT  2.16 12.015 21.6 12.285 ;
     RECT  2.16 12.555 21.6 12.825 ;
     RECT  2.16 13.095 21.6 13.365 ;
     RECT  2.16 13.635 21.6 13.905 ;
     RECT  2.16 14.175 21.6 14.445 ;
     RECT  2.16 14.715 21.6 14.985 ;
     RECT  2.16 15.255 21.6 15.525 ;
     RECT  2.16 15.795 21.6 16.065 ;
     RECT  2.16 16.335 21.6 16.605 ;
     RECT  2.16 16.875 21.6 17.145 ;
     RECT  2.16 17.415 21.6 17.685 ;
     RECT  2.16 17.955 21.6 18.225 ;
     RECT  2.16 18.495 21.6 18.765 ;
     RECT  2.16 19.035 21.6 19.305 ;
     RECT  2.16 19.575 21.6 19.845 ;
     RECT  2.16 20.115 21.6 20.385 ;
     RECT  2.16 20.655 21.6 20.925 ;
     RECT  2.16 21.195 21.6 21.465 ;
    LAYER M1 ;
     RECT  2.16 2.151 21.6 21.609 ;
    LAYER M2 ;
     RECT  0.067 6.786 0.103 6.804 ;
     RECT  0.031 8.982 0.103 9 ;
     RECT  0.067 10.134 0.103 10.152 ;
     RECT  0.103 6.282 0.139 6.984 ;
     RECT  0.103 4.968 0.175 4.986 ;
     RECT  0.103 8.982 0.275 9.072 ;
     RECT  0.103 10.134 0.319 10.656 ;
     RECT  0.175 4.662 0.383 4.986 ;
     RECT  0.139 6.282 0.535 7.524 ;
     RECT  0.031 11.718 0.859 11.736 ;
     RECT  0.103 12.492 0.859 12.51 ;
     RECT  0.319 9.828 0.931 10.656 ;
     RECT  0.859 11.718 0.931 12.51 ;
     RECT  0.931 9.828 1.147 12.51 ;
     RECT  0.571 8.586 1.183 8.604 ;
     RECT  1.147 9.558 1.183 12.51 ;
     RECT  1.723 3.852 1.759 3.87 ;
     RECT  0.535 5.85 2.011 7.524 ;
     RECT  1.183 8.586 2.011 12.51 ;
     RECT  1.759 3.816 2.16 3.87 ;
     RECT  0.383 4.662 2.16 4.914 ;
     RECT  2.011 5.85 2.16 12.51 ;
     RECT  2.16 2.151 2.947 21.609 ;
     RECT  2.947 2.106 5.459 21.609 ;
     RECT  5.459 2.151 6.331 21.609 ;
     RECT  6.331 1.656 7.195 21.609 ;
     RECT  7.267 0.036 7.447 0.054 ;
     RECT  7.195 1.611 8.131 21.609 ;
     RECT  8.131 1.152 8.411 21.609 ;
     RECT  7.447 0.036 8.563 0.162 ;
     RECT  8.563 0.036 9.139 0.864 ;
     RECT  8.411 1.611 9.139 21.609 ;
     RECT  9.139 0.036 10.579 21.609 ;
     RECT  10.579 0.036 11.903 21.654 ;
     RECT  11.903 0.036 13.055 0.09 ;
     RECT  11.903 0.846 13.415 21.654 ;
     RECT  13.415 0.954 13.559 21.654 ;
     RECT  13.559 1.611 14.171 21.654 ;
     RECT  14.171 1.611 14.315 21.609 ;
     RECT  13.055 0.036 14.387 0.054 ;
     RECT  14.315 1.692 14.819 21.609 ;
     RECT  14.819 2.151 16.087 21.609 ;
     RECT  16.087 2.151 21.155 21.654 ;
     RECT  21.155 2.151 21.6 21.609 ;
     RECT  21.6 6.156 22.307 8.226 ;
     RECT  22.307 6.624 22.523 8.226 ;
     RECT  22.523 6.66 22.811 8.226 ;
     RECT  22.811 6.822 22.847 7.686 ;
     RECT  22.847 7.668 22.883 7.686 ;
     RECT  22.847 6.822 23.675 6.84 ;
    LAYER M3 ;
     RECT  7.272 0.031 7.29 0.067 ;
     RECT  7.272 0.067 7.686 0.091 ;
     RECT  13.032 0.067 13.05 0.091 ;
     RECT  6.984 0.091 7.686 0.139 ;
     RECT  11.88 0.103 11.898 0.139 ;
     RECT  12.852 0.091 13.05 0.139 ;
     RECT  6.264 0.139 7.686 0.173 ;
     RECT  4.464 0.091 5.094 0.221 ;
     RECT  8.136 0.187 8.154 0.235 ;
     RECT  12.708 0.139 13.05 0.235 ;
     RECT  4.464 0.221 4.482 0.269 ;
     RECT  6.264 0.173 7.002 0.269 ;
     RECT  8.136 0.235 8.586 0.283 ;
     RECT  9.684 0.235 9.81 0.283 ;
     RECT  11.232 0.139 11.898 0.331 ;
     RECT  12.672 0.235 13.05 0.331 ;
     RECT  8.136 0.283 8.658 0.475 ;
     RECT  9.684 0.283 10.386 0.475 ;
     RECT  11.232 0.331 13.05 0.811 ;
     RECT  11.232 0.811 13.374 0.841 ;
     RECT  11.232 0.841 13.41 0.949 ;
     RECT  3.312 0.907 3.33 1.003 ;
     RECT  6.516 0.269 7.002 1.099 ;
     RECT  8.136 0.475 10.386 1.099 ;
     RECT  6.516 1.099 10.386 1.147 ;
     RECT  11.232 0.949 13.554 1.147 ;
     RECT  6.516 1.147 13.554 1.175 ;
     RECT  3.312 1.003 3.402 1.195 ;
     RECT  14.364 0.031 14.382 1.606 ;
     RECT  6.516 1.175 9.774 1.651 ;
     RECT  10.512 1.175 13.554 1.651 ;
     RECT  14.292 1.606 14.382 1.651 ;
     RECT  3.312 1.195 3.942 1.675 ;
     RECT  10.512 1.651 14.382 1.675 ;
     RECT  10.512 1.675 14.49 1.687 ;
     RECT  2.808 1.675 3.942 1.723 ;
     RECT  0.18 1.579 0.198 1.771 ;
     RECT  0.972 0.811 0.99 1.771 ;
     RECT  2.808 1.723 5.058 1.771 ;
     RECT  6.336 1.651 9.774 1.771 ;
     RECT  0.18 1.771 0.99 1.915 ;
     RECT  2.808 1.771 9.774 1.921 ;
     RECT  10.512 1.687 14.814 1.921 ;
     RECT  1.728 1.387 1.746 1.963 ;
     RECT  2.808 1.921 14.814 1.963 ;
     RECT  0.144 1.915 0.99 2.155 ;
     RECT  1.728 1.963 14.814 2.155 ;
     RECT  0.144 2.155 14.814 2.285 ;
     RECT  18.615 2.143 18.705 2.413 ;
     RECT  0.18 2.285 14.814 3.403 ;
     RECT  18.615 2.413 18.897 3.415 ;
     RECT  0.144 3.403 14.814 3.451 ;
     RECT  18.615 3.415 18.99 3.451 ;
     RECT  18.615 3.451 19.062 3.613 ;
     RECT  19.8 3.595 19.818 3.613 ;
     RECT  0.144 3.451 14.994 3.677 ;
     RECT  18.615 3.613 19.818 3.721 ;
     RECT  18.615 3.721 20.178 4.351 ;
     RECT  17.316 4.423 17.334 4.495 ;
     RECT  18.252 4.351 20.178 4.495 ;
     RECT  17.316 4.495 17.406 4.657 ;
     RECT  18.252 4.495 20.286 4.657 ;
     RECT  0.18 3.677 14.994 4.684 ;
     RECT  17.316 4.657 20.286 4.729 ;
     RECT  0.144 4.684 14.994 4.939 ;
     RECT  17.136 4.729 20.286 5.071 ;
     RECT  16.236 5.071 16.254 5.233 ;
     RECT  17.028 5.071 20.286 5.233 ;
     RECT  16.236 5.233 20.286 5.269 ;
     RECT  0.108 4.939 14.994 5.707 ;
     RECT  0.108 5.707 15.318 5.881 ;
     RECT  16.056 5.269 20.286 5.881 ;
     RECT  22.284 6.151 22.302 6.241 ;
     RECT  0.108 5.881 20.538 6.421 ;
     RECT  22.248 6.241 22.302 6.619 ;
     RECT  22.248 6.619 22.518 6.655 ;
     RECT  22.248 6.655 22.806 6.691 ;
     RECT  22.212 6.691 22.806 6.701 ;
     RECT  0.108 6.421 21.006 6.781 ;
     RECT  0.072 6.781 21.006 6.817 ;
     RECT  23.652 6.817 23.67 6.893 ;
     RECT  0.072 6.817 21.042 6.925 ;
     RECT  0.072 6.925 21.294 6.953 ;
     RECT  14.688 6.953 21.294 6.955 ;
     RECT  22.212 6.701 22.734 6.955 ;
     RECT  14.688 6.955 22.734 7.501 ;
     RECT  14.688 7.501 22.842 7.565 ;
     RECT  22.5 7.565 22.842 7.663 ;
     RECT  14.688 7.565 21.762 7.763 ;
     RECT  0.072 6.953 13.95 7.861 ;
     RECT  14.688 7.763 21.69 7.861 ;
     RECT  22.5 7.663 22.878 8.045 ;
     RECT  0.072 7.861 21.69 8.141 ;
     RECT  22.5 8.045 22.806 8.231 ;
     RECT  22.5 8.231 22.518 8.333 ;
     RECT  0.072 8.141 21.438 8.501 ;
     RECT  0.072 8.501 17.154 8.977 ;
     RECT  17.964 8.501 21.438 9.121 ;
     RECT  17.964 9.121 21.474 9.239 ;
     RECT  0.036 8.977 17.154 9.259 ;
     RECT  0.036 9.259 17.226 9.391 ;
     RECT  17.964 9.239 21.042 9.391 ;
     RECT  0.036 9.391 21.042 10.165 ;
     RECT  0.036 10.165 21.114 10.319 ;
     RECT  0.036 10.319 21.042 10.463 ;
     RECT  0.036 10.463 20.97 10.685 ;
     RECT  0.828 10.685 20.97 11.165 ;
     RECT  16.236 11.165 20.97 11.281 ;
     RECT  0.828 11.165 15.39 11.705 ;
     RECT  0.036 10.685 0.054 11.741 ;
     RECT  0.828 11.705 0.882 11.741 ;
     RECT  0.864 11.741 0.882 11.975 ;
     RECT  2.304 11.705 15.39 12.055 ;
     RECT  16.236 11.281 21.474 12.055 ;
     RECT  2.304 12.055 21.474 12.209 ;
     RECT  0.108 12.487 0.126 12.653 ;
     RECT  2.304 12.209 21.366 13.019 ;
     RECT  0.144 12.907 0.162 13.085 ;
     RECT  2.304 13.019 20.862 13.483 ;
     RECT  2.268 13.483 20.862 13.595 ;
     RECT  2.304 13.595 20.862 13.945 ;
     RECT  2.304 13.945 20.934 13.981 ;
     RECT  2.304 13.981 21.042 14.135 ;
     RECT  2.415 14.135 21.042 14.369 ;
     RECT  3.888 14.369 21.042 14.521 ;
     RECT  3.888 14.521 21.402 14.747 ;
     RECT  2.415 14.369 3.078 14.783 ;
     RECT  4.068 14.747 21.042 14.783 ;
     RECT  4.644 14.783 21.042 15.601 ;
     RECT  3.852 15.835 3.87 15.871 ;
     RECT  4.644 15.601 21.078 15.871 ;
     RECT  3.852 15.871 21.078 16.141 ;
     RECT  3.852 16.141 21.474 16.259 ;
     RECT  3.852 16.259 21.366 16.943 ;
     RECT  3.852 16.943 21.186 17.609 ;
     RECT  3.852 17.609 21.042 18.185 ;
     RECT  4.788 18.185 21.042 18.221 ;
     RECT  7.524 18.221 21.042 18.571 ;
     RECT  7.524 18.571 21.15 18.689 ;
     RECT  3.852 18.185 3.87 19.031 ;
     RECT  4.788 18.221 6.786 19.111 ;
     RECT  7.524 18.689 21.042 19.111 ;
     RECT  4.032 19.111 4.05 19.337 ;
     RECT  4.788 19.111 21.042 19.921 ;
     RECT  4.14 19.921 21.042 20.039 ;
     RECT  4.824 20.039 21.042 20.183 ;
     RECT  3.96 20.155 3.978 20.573 ;
     RECT  4.896 20.183 21.042 20.579 ;
     RECT  4.896 20.579 9.594 20.615 ;
     RECT  4.896 20.615 9.234 20.687 ;
     RECT  4.896 20.687 9.018 20.885 ;
     RECT  5.184 20.885 5.85 20.921 ;
     RECT  6.84 20.885 6.894 20.921 ;
     RECT  5.184 20.921 5.202 21.029 ;
     RECT  6.876 20.921 6.894 21.029 ;
     RECT  7.815 20.885 9.018 21.119 ;
     RECT  10.332 20.579 21.042 21.149 ;
     RECT  7.815 21.119 8.91 21.155 ;
     RECT  10.332 21.149 20.178 21.155 ;
     RECT  20.988 21.149 21.042 21.263 ;
     RECT  2.415 14.783 2.697 21.347 ;
     RECT  7.815 21.155 8.097 21.347 ;
     RECT  10.44 21.155 20.178 21.389 ;
     RECT  21.024 21.263 21.042 21.389 ;
     RECT  20.052 21.389 20.178 21.485 ;
     RECT  20.088 21.485 20.178 21.569 ;
     RECT  2.415 21.347 2.505 21.617 ;
     RECT  7.815 21.347 7.905 21.617 ;
     RECT  18.615 21.389 19.278 21.617 ;
     RECT  10.44 21.389 17.694 21.659 ;
     RECT  21.132 21.505 21.15 21.659 ;
     RECT  10.44 21.659 17.082 21.677 ;
     RECT  20.088 21.569 20.106 21.677 ;
     RECT  10.44 21.677 12.33 21.725 ;
     RECT  13.068 21.677 13.59 21.725 ;
     RECT  18.756 21.617 19.278 21.725 ;
     RECT  12.312 21.725 12.33 21.773 ;
     RECT  10.44 21.725 11.466 21.821 ;
     RECT  13.068 21.725 13.086 21.821 ;
     RECT  11.268 21.821 11.466 22.205 ;
     RECT  15.444 21.677 15.462 22.781 ;
     RECT  10.44 21.821 10.458 22.829 ;
     RECT  11.448 22.205 11.466 23.549 ;
     RECT  15.156 23.515 15.174 23.645 ;
    LAYER M4 ;
     RECT  0.084 12.432 0.817 12.456 ;
     RECT  0.06 12.456 0.817 12.528 ;
     RECT  0.084 12.528 0.817 12.552 ;
     RECT  0.06 12.552 0.817 12.624 ;
     RECT  0.084 12.624 0.817 12.648 ;
     RECT  0.06 12.648 0.817 12.72 ;
     RECT  0.084 12.72 0.817 12.744 ;
     RECT  0.06 12.744 0.817 12.816 ;
     RECT  0.084 12.816 0.817 12.84 ;
     RECT  0.06 12.84 0.817 12.912 ;
     RECT  0.084 12.912 0.817 12.936 ;
     RECT  0.06 12.936 0.817 13.008 ;
     RECT  0.084 13.008 0.817 13.032 ;
     RECT  0.06 13.032 0.817 13.104 ;
     RECT  0.084 13.104 0.817 13.128 ;
     RECT  0.06 13.128 0.817 13.2 ;
     RECT  0.084 13.2 0.817 13.224 ;
     RECT  0.06 13.224 0.817 13.296 ;
     RECT  0.084 13.296 0.817 13.32 ;
     RECT  0.06 13.32 0.817 13.392 ;
     RECT  0.084 13.392 0.817 13.416 ;
     RECT  0.06 13.416 0.817 13.488 ;
     RECT  0.084 13.488 0.817 13.512 ;
     RECT  0.06 13.512 0.817 13.584 ;
     RECT  0.084 13.584 0.817 13.608 ;
     RECT  0.06 13.608 0.817 13.68 ;
     RECT  0.084 13.68 0.817 13.704 ;
     RECT  0.06 13.704 0.817 13.776 ;
     RECT  0.084 13.776 0.817 13.8 ;
     RECT  0.084 0.816 1.001 0.84 ;
     RECT  0.06 0.84 1.001 0.912 ;
     RECT  0.084 0.912 1.001 0.936 ;
     RECT  0.06 0.936 1.001 1.008 ;
     RECT  0.084 1.008 1.001 1.032 ;
     RECT  0.06 1.032 1.001 1.104 ;
     RECT  0.084 1.104 1.001 1.128 ;
     RECT  0.06 1.128 1.001 1.2 ;
     RECT  0.084 1.2 1.001 1.224 ;
     RECT  0.06 1.224 1.001 1.296 ;
     RECT  0.084 1.296 1.001 1.32 ;
     RECT  0.06 1.32 1.001 1.392 ;
     RECT  0.084 1.392 1.001 1.416 ;
     RECT  0.06 1.416 1.001 1.488 ;
     RECT  0.084 1.488 1.001 1.512 ;
     RECT  0.06 1.512 1.001 1.584 ;
     RECT  0.084 1.584 1.001 1.608 ;
     RECT  0.06 1.608 1.001 1.68 ;
     RECT  0.084 1.68 1.001 1.704 ;
     RECT  0.06 1.704 1.001 1.776 ;
     RECT  0.084 1.776 1.001 1.8 ;
     RECT  0.06 1.8 1.001 1.872 ;
     RECT  0.084 1.872 1.001 1.896 ;
     RECT  0.06 1.896 1.001 1.968 ;
     RECT  0.084 1.968 1.001 1.992 ;
     RECT  0.06 1.992 1.001 2.064 ;
     RECT  0.084 2.064 1.001 2.088 ;
     RECT  0.06 2.088 1.001 2.16 ;
     RECT  0.084 2.16 1.001 2.184 ;
     RECT  0.06 2.184 1.001 2.256 ;
     RECT  0.084 2.256 1.001 2.28 ;
     RECT  0.06 2.28 1.001 2.352 ;
     RECT  0.084 2.352 1.001 2.376 ;
     RECT  0.06 2.376 1.001 2.448 ;
     RECT  0.084 2.448 1.001 2.472 ;
     RECT  0.06 2.472 1.001 2.544 ;
     RECT  0.084 2.544 1.001 2.568 ;
     RECT  0.06 2.568 1.001 2.64 ;
     RECT  0.084 2.64 1.001 2.664 ;
     RECT  0.06 2.664 1.001 2.736 ;
     RECT  0.084 2.736 1.001 2.76 ;
     RECT  0.06 2.76 1.001 2.832 ;
     RECT  0.084 2.832 1.001 2.856 ;
     RECT  0.06 2.856 1.001 2.928 ;
     RECT  0.084 2.928 1.001 2.952 ;
     RECT  0.06 2.952 1.001 3.024 ;
     RECT  0.084 3.024 1.001 3.048 ;
     RECT  0.06 3.048 1.001 3.12 ;
     RECT  0.084 3.12 1.001 3.144 ;
     RECT  0.06 3.144 1.001 3.216 ;
     RECT  0.084 3.216 1.001 3.24 ;
     RECT  0.06 3.24 1.001 3.312 ;
     RECT  0.084 3.312 1.001 3.336 ;
     RECT  0.06 3.336 1.001 3.408 ;
     RECT  0.084 3.408 1.001 3.432 ;
     RECT  0.06 3.432 1.001 3.504 ;
     RECT  0.084 3.504 1.001 3.528 ;
     RECT  0.06 3.528 1.001 3.6 ;
     RECT  0.084 3.6 1.001 3.624 ;
     RECT  0.06 3.624 1.001 3.696 ;
     RECT  0.084 3.696 1.001 3.72 ;
     RECT  0.06 3.72 1.001 3.792 ;
     RECT  0.084 3.792 1.001 3.816 ;
     RECT  0.06 3.816 1.001 4.656 ;
     RECT  0.084 4.656 1.001 4.68 ;
     RECT  0.06 4.68 1.001 4.752 ;
     RECT  0.084 4.752 1.001 4.776 ;
     RECT  0.06 4.776 1.001 4.848 ;
     RECT  0.084 4.848 1.001 4.872 ;
     RECT  0.06 4.872 1.001 4.944 ;
     RECT  0.084 4.944 1.001 4.968 ;
     RECT  0.06 4.968 1.001 5.04 ;
     RECT  0.084 5.04 1.001 5.064 ;
     RECT  0.06 5.064 1.001 5.136 ;
     RECT  0.084 5.136 1.001 5.16 ;
     RECT  0.06 5.16 1.001 5.232 ;
     RECT  0.084 5.232 1.001 5.256 ;
     RECT  0.06 5.256 1.001 5.328 ;
     RECT  0.084 5.328 1.001 5.352 ;
     RECT  0.06 5.352 1.001 5.424 ;
     RECT  0.084 5.424 1.001 5.448 ;
     RECT  0.06 5.448 1.001 5.52 ;
     RECT  0.084 5.52 1.001 5.544 ;
     RECT  0.06 5.544 1.001 5.616 ;
     RECT  0.084 5.616 1.001 5.64 ;
     RECT  0.06 5.64 1.001 5.712 ;
     RECT  0.084 5.712 1.001 5.736 ;
     RECT  0.06 5.736 1.001 5.808 ;
     RECT  0.084 5.808 1.001 5.832 ;
     RECT  0.06 5.832 1.001 5.904 ;
     RECT  0.084 5.904 1.001 5.928 ;
     RECT  0.06 5.928 1.001 6 ;
     RECT  0.084 6 1.001 6.024 ;
     RECT  0.06 6.024 1.001 6.096 ;
     RECT  0.084 6.096 1.001 6.12 ;
     RECT  0.06 6.12 1.001 6.192 ;
     RECT  0.084 6.192 1.001 6.216 ;
     RECT  0.06 6.216 1.001 6.288 ;
     RECT  0.084 6.288 1.001 6.312 ;
     RECT  0.06 6.312 1.001 6.384 ;
     RECT  0.084 6.384 1.001 6.408 ;
     RECT  0.06 6.408 1.001 6.48 ;
     RECT  0.084 6.48 1.001 6.504 ;
     RECT  0.06 6.504 1.001 6.576 ;
     RECT  0.084 6.576 1.001 6.6 ;
     RECT  0.06 6.6 1.001 6.672 ;
     RECT  0.084 6.672 1.001 6.696 ;
     RECT  0.06 6.696 1.001 6.768 ;
     RECT  0.084 6.768 1.001 6.792 ;
     RECT  0.06 6.792 1.001 6.864 ;
     RECT  0.084 6.864 1.001 6.888 ;
     RECT  0.06 6.888 1.001 6.96 ;
     RECT  0.084 6.96 1.001 6.984 ;
     RECT  0.06 6.984 1.001 7.056 ;
     RECT  0.084 7.056 1.001 7.08 ;
     RECT  0.06 7.08 1.001 7.152 ;
     RECT  0.084 7.152 1.001 7.176 ;
     RECT  0.06 7.176 1.001 7.248 ;
     RECT  0.084 7.248 1.001 7.272 ;
     RECT  0.06 7.272 1.001 7.344 ;
     RECT  0.084 7.344 1.001 7.368 ;
     RECT  0.06 7.368 1.001 7.44 ;
     RECT  0.084 7.44 1.001 7.464 ;
     RECT  0.06 7.464 1.001 7.536 ;
     RECT  0.084 7.536 1.001 7.56 ;
     RECT  0.06 7.56 1.001 7.632 ;
     RECT  0.084 7.632 1.001 7.656 ;
     RECT  0.06 7.656 1.001 7.728 ;
     RECT  0.084 7.728 1.001 7.752 ;
     RECT  0.06 7.752 1.001 7.824 ;
     RECT  0.084 7.824 1.001 7.848 ;
     RECT  0.06 7.848 1.001 7.92 ;
     RECT  0.084 7.92 1.001 7.944 ;
     RECT  0.06 7.944 1.001 8.016 ;
     RECT  0.084 8.016 1.001 8.04 ;
     RECT  0.06 8.04 1.001 8.112 ;
     RECT  0.084 8.112 1.001 8.136 ;
     RECT  0.06 8.136 1.001 8.208 ;
     RECT  0.084 8.208 1.001 8.232 ;
     RECT  0.06 8.232 1.001 8.304 ;
     RECT  0.084 8.304 1.001 8.328 ;
     RECT  0.06 8.328 1.001 8.4 ;
     RECT  0.084 8.4 1.001 8.424 ;
     RECT  0.06 8.424 1.001 8.496 ;
     RECT  0.084 8.496 1.001 8.52 ;
     RECT  0.06 8.52 1.001 8.592 ;
     RECT  0.084 8.592 1.001 8.616 ;
     RECT  0.06 8.616 1.001 8.688 ;
     RECT  0.084 8.688 1.001 8.712 ;
     RECT  0.06 8.712 1.001 8.784 ;
     RECT  0.084 8.784 1.001 8.808 ;
     RECT  0.06 8.808 1.001 8.88 ;
     RECT  0.084 8.88 1.001 8.904 ;
     RECT  0.06 8.904 1.001 8.976 ;
     RECT  0.084 8.976 1.001 9 ;
     RECT  0.06 9 1.001 9.072 ;
     RECT  0.084 9.072 1.001 9.096 ;
     RECT  0.06 9.096 1.001 9.168 ;
     RECT  0.084 9.168 1.001 9.192 ;
     RECT  0.06 9.192 1.001 9.264 ;
     RECT  0.084 9.264 1.001 9.288 ;
     RECT  0.06 9.288 1.001 9.36 ;
     RECT  0.084 9.36 1.001 9.384 ;
     RECT  0.06 9.384 1.001 9.456 ;
     RECT  0.084 9.456 1.001 9.48 ;
     RECT  0.06 9.48 1.001 9.552 ;
     RECT  0.084 9.552 1.001 9.576 ;
     RECT  0.06 9.576 1.001 9.648 ;
     RECT  0.084 9.648 1.001 9.672 ;
     RECT  0.06 9.672 1.001 9.744 ;
     RECT  0.084 9.744 1.001 9.768 ;
     RECT  0.06 9.768 1.001 9.84 ;
     RECT  0.084 9.84 1.001 9.864 ;
     RECT  0.06 9.864 1.001 9.936 ;
     RECT  0.084 9.936 1.001 9.96 ;
     RECT  0.06 9.96 1.001 10.032 ;
     RECT  0.084 10.032 1.001 10.056 ;
     RECT  0.06 10.056 1.001 10.128 ;
     RECT  0.084 10.128 1.001 10.152 ;
     RECT  0.06 10.152 1.001 10.224 ;
     RECT  0.084 10.224 1.001 10.248 ;
     RECT  0.06 10.248 1.001 10.32 ;
     RECT  0.084 10.32 1.001 10.344 ;
     RECT  0.06 10.344 1.001 10.416 ;
     RECT  0.084 10.416 1.001 10.44 ;
     RECT  0.06 10.44 1.001 10.512 ;
     RECT  0.084 10.512 1.001 10.536 ;
     RECT  0.06 10.536 1.001 10.608 ;
     RECT  0.084 10.608 1.001 10.632 ;
     RECT  0.06 10.632 1.001 10.704 ;
     RECT  0.084 10.704 1.001 10.728 ;
     RECT  1.001 0.912 2.257 10.728 ;
     RECT  0.817 11.712 2.257 13.8 ;
     RECT  2.257 0.912 2.408 13.8 ;
     RECT  2.408 0.912 2.512 21.612 ;
     RECT  2.512 0.912 2.704 21.342 ;
     RECT  2.704 0.912 3.341 14.28 ;
     RECT  3.341 1.008 3.709 14.28 ;
     RECT  3.709 1.008 3.953 14.184 ;
     RECT  4.357 0.336 4.405 0.36 ;
     RECT  4.405 0.24 4.453 0.36 ;
     RECT  4.417 16.32 4.453 16.344 ;
     RECT  4.453 0.096 4.547 0.36 ;
     RECT  3.953 1.488 4.693 14.184 ;
     RECT  4.693 1.488 4.817 14.856 ;
     RECT  4.547 0.096 5.105 0.312 ;
     RECT  5.105 0.144 5.171 0.312 ;
     RECT  5.317 19.344 6.001 19.368 ;
     RECT  4.817 1.488 6.037 14.136 ;
     RECT  6.001 19.344 6.073 19.56 ;
     RECT  3.949 20.544 6.073 20.568 ;
     RECT  4.453 16.32 6.085 17.064 ;
     RECT  6.085 16.272 6.131 17.064 ;
     RECT  5.171 0.144 6.277 0.264 ;
     RECT  6.037 1.488 6.277 14.232 ;
     RECT  5.749 18.192 6.325 18.216 ;
     RECT  6.073 19.344 6.325 20.568 ;
     RECT  6.325 18.192 6.329 20.568 ;
     RECT  6.329 18.192 6.473 19.608 ;
     RECT  6.131 16.272 6.685 16.872 ;
     RECT  6.277 0.144 6.757 14.232 ;
     RECT  6.685 15.792 6.965 16.872 ;
     RECT  6.473 19.392 7.693 19.608 ;
     RECT  6.757 0.096 7.808 14.232 ;
     RECT  6.965 15.408 7.808 16.872 ;
     RECT  6.473 18.192 7.808 18.216 ;
     RECT  7.693 19.392 7.808 20.424 ;
     RECT  7.808 0.096 7.912 21.612 ;
     RECT  7.912 0.096 8.104 21.342 ;
     RECT  8.104 0.096 8.165 13.704 ;
     RECT  8.165 0.096 8.243 13.56 ;
     RECT  8.243 0.096 9.205 11.832 ;
     RECT  8.104 14.688 9.209 17.16 ;
     RECT  9.205 0.096 9.317 11.976 ;
     RECT  9.317 0.096 9.389 11.4 ;
     RECT  8.104 20.4 9.421 20.424 ;
     RECT  8.243 13.104 9.461 13.56 ;
     RECT  9.389 0.096 9.497 10.68 ;
     RECT  9.497 0.096 9.677 9.96 ;
     RECT  9.677 0.096 9.785 9.624 ;
     RECT  9.209 14.784 9.853 17.16 ;
     RECT  9.461 13.104 10.109 13.128 ;
     RECT  9.853 14.784 10.465 17.736 ;
     RECT  9.421 19.488 10.573 20.424 ;
     RECT  10.465 14.784 10.577 18.456 ;
     RECT  10.573 19.488 10.645 21.048 ;
     RECT  9.785 0.096 10.825 9.384 ;
     RECT  10.429 22.8 10.835 22.824 ;
     RECT  10.645 19.488 10.897 21.72 ;
     RECT  10.933 11.424 11.069 11.448 ;
     RECT  10.825 13.536 11.149 13.608 ;
     RECT  11.149 13.536 11.257 14.28 ;
     RECT  10.897 19.488 11.257 21.816 ;
     RECT  10.577 15.504 11.329 18.456 ;
     RECT  11.257 13.104 11.401 14.28 ;
     RECT  11.069 11.424 11.473 11.736 ;
     RECT  11.401 12.768 11.473 14.28 ;
     RECT  11.329 15.504 11.581 18.504 ;
     RECT  11.257 19.488 11.581 22.2 ;
     RECT  11.473 11.424 11.941 14.28 ;
     RECT  11.941 11.232 11.977 14.28 ;
     RECT  10.825 0.096 12.035 9.912 ;
     RECT  11.977 11.232 12.517 14.328 ;
     RECT  11.581 15.504 12.517 22.2 ;
     RECT  12.035 0.096 12.881 7.944 ;
     RECT  12.881 0.816 13.045 7.944 ;
     RECT  12.035 9.024 13.045 9.912 ;
     RECT  13.045 0.816 13.208 9.912 ;
     RECT  12.517 11.232 13.208 22.2 ;
     RECT  11.437 23.52 13.285 23.544 ;
     RECT  13.208 0.816 13.385 22.2 ;
     RECT  13.385 1.68 13.523 22.2 ;
     RECT  13.523 1.68 13.601 21.72 ;
     RECT  13.285 23.424 13.619 23.544 ;
     RECT  13.601 1.68 13.781 21.672 ;
     RECT  13.781 1.68 14.141 13.8 ;
     RECT  14.141 1.68 14.213 11.256 ;
     RECT  14.213 3.36 14.321 5.832 ;
     RECT  14.213 6.912 14.357 11.256 ;
     RECT  14.213 1.68 14.429 2.04 ;
     RECT  14.357 10.176 14.465 11.256 ;
     RECT  14.429 1.68 14.501 1.704 ;
     RECT  14.321 3.36 14.537 4.44 ;
     RECT  14.357 6.912 14.573 9.144 ;
     RECT  14.537 3.36 14.609 4.2 ;
     RECT  14.609 3.36 14.789 4.104 ;
     RECT  14.141 12.336 14.821 13.8 ;
     RECT  13.781 14.784 14.821 21.672 ;
     RECT  14.789 3.456 14.825 4.008 ;
     RECT  14.573 7.344 15.077 9.144 ;
     RECT  13.765 23.568 15.106 23.592 ;
     RECT  14.821 12.336 15.181 21.672 ;
     RECT  14.465 10.176 15.185 10.872 ;
     RECT  15.106 23.52 15.205 23.64 ;
     RECT  15.181 12.24 15.293 21.672 ;
     RECT  15.205 22.752 15.347 23.64 ;
     RECT  15.347 22.752 15.473 23.592 ;
     RECT  14.321 5.424 15.637 5.832 ;
     RECT  15.293 12.24 15.725 12.264 ;
     RECT  15.637 5.424 15.761 6.264 ;
     RECT  15.185 10.176 15.865 10.2 ;
     RECT  15.077 7.344 15.901 8.568 ;
     RECT  15.901 7.152 15.905 8.568 ;
     RECT  15.865 9.84 16.369 10.2 ;
     RECT  15.473 23.568 16.451 23.592 ;
     RECT  16.369 9.84 16.693 10.824 ;
     RECT  15.293 13.296 16.909 21.672 ;
     RECT  15.761 5.424 17.017 5.832 ;
     RECT  16.837 23.616 17.027 23.64 ;
     RECT  16.693 9.84 17.057 11.448 ;
     RECT  16.909 12.528 17.075 21.672 ;
     RECT  15.905 7.152 17.089 7.944 ;
     RECT  17.075 20.592 17.093 21.672 ;
     RECT  17.075 12.528 17.123 19.032 ;
     RECT  17.057 9.84 17.197 9.864 ;
     RECT  17.197 9.264 17.237 9.864 ;
     RECT  17.089 6.864 17.269 7.944 ;
     RECT  17.017 5.328 18.037 5.832 ;
     RECT  17.269 6.864 18.169 8.088 ;
     RECT  18.037 5.088 18.241 5.832 ;
     RECT  18.169 6.816 18.241 8.088 ;
     RECT  17.057 10.848 18.284 11.448 ;
     RECT  18.284 10.56 18.313 11.448 ;
     RECT  18.241 5.088 18.457 8.088 ;
     RECT  17.237 9.264 18.457 9.288 ;
     RECT  14.825 3.6 18.608 3.624 ;
     RECT  18.457 5.088 18.608 9.288 ;
     RECT  18.313 10.56 18.608 11.976 ;
     RECT  17.123 13.104 18.608 19.032 ;
     RECT  17.093 20.592 18.608 21.48 ;
     RECT  18.608 2.148 18.712 21.612 ;
     RECT  18.712 2.418 18.716 21.612 ;
     RECT  18.716 2.418 18.904 21.72 ;
     RECT  18.904 10.176 19.001 11.688 ;
     RECT  18.904 13.392 19.181 13.704 ;
     RECT  18.904 5.856 19.217 8.424 ;
     RECT  18.853 23.568 19.235 23.592 ;
     RECT  19.181 13.392 19.289 13.656 ;
     RECT  18.904 20.448 19.289 21.72 ;
     RECT  19.001 10.608 19.469 11.688 ;
     RECT  19.469 10.608 19.505 10.632 ;
     RECT  19.289 13.632 19.613 13.656 ;
     RECT  19.469 11.664 19.757 11.688 ;
     RECT  18.904 3.6 19.829 3.624 ;
     RECT  18.904 14.976 20.005 19.032 ;
     RECT  19.289 20.448 20.005 21.672 ;
     RECT  20.005 14.976 20.117 21.672 ;
     RECT  19.217 6.816 20.189 8.424 ;
     RECT  20.117 14.976 20.189 21.144 ;
     RECT  20.189 14.976 20.369 15.624 ;
     RECT  20.189 17.184 20.441 21.144 ;
     RECT  20.189 6.816 20.585 7.848 ;
     RECT  20.441 17.184 20.621 19.032 ;
     RECT  20.621 19.008 20.657 19.032 ;
     RECT  20.441 20.208 20.693 21.144 ;
     RECT  20.653 14.832 20.765 14.856 ;
     RECT  20.693 20.208 20.765 20.232 ;
     RECT  20.621 17.184 21.053 17.976 ;
     RECT  20.585 7.248 21.157 7.848 ;
     RECT  21.053 17.184 21.197 17.208 ;
     RECT  21.157 7.248 21.661 8.232 ;
     RECT  21.661 6.96 22.201 8.232 ;
     RECT  22.201 6.768 22.237 8.232 ;
     RECT  22.237 6.48 22.489 8.232 ;
     RECT  22.489 6.48 23.676 6.504 ;
     RECT  22.489 6.504 23.724 6.576 ;
     RECT  22.489 6.576 23.676 6.6 ;
     RECT  22.489 6.6 23.724 6.672 ;
     RECT  22.489 6.672 23.676 6.696 ;
     RECT  22.489 6.696 23.724 6.768 ;
     RECT  22.489 6.768 23.676 6.792 ;
     RECT  22.489 6.792 23.724 6.864 ;
     RECT  22.489 6.864 23.676 6.888 ;
     RECT  22.489 6.888 23.724 6.96 ;
     RECT  22.489 6.96 23.676 6.984 ;
     RECT  22.489 6.984 23.724 7.056 ;
     RECT  22.489 7.056 23.676 7.08 ;
     RECT  22.489 7.08 23.724 7.152 ;
     RECT  22.489 7.152 23.676 7.176 ;
     RECT  22.489 7.176 23.724 7.248 ;
     RECT  22.489 7.248 23.676 7.272 ;
     RECT  22.489 7.272 23.724 7.344 ;
     RECT  22.489 7.344 23.676 7.368 ;
     RECT  22.489 7.368 23.724 7.44 ;
     RECT  22.489 7.44 23.676 7.464 ;
     RECT  22.489 7.464 23.724 7.536 ;
     RECT  22.489 7.536 23.676 7.56 ;
     RECT  22.489 7.56 23.724 7.632 ;
     RECT  22.489 7.632 23.676 7.656 ;
     RECT  22.489 7.656 23.724 7.728 ;
     RECT  22.489 7.728 23.676 7.752 ;
     RECT  22.489 7.752 23.724 7.824 ;
     RECT  22.489 7.824 23.676 7.848 ;
     RECT  22.489 7.848 23.724 7.92 ;
     RECT  22.489 7.92 23.676 7.944 ;
     RECT  22.489 7.944 23.724 8.016 ;
     RECT  22.489 8.016 23.676 8.04 ;
     RECT  22.489 8.04 23.724 8.112 ;
     RECT  22.489 8.112 23.676 8.136 ;
     RECT  22.489 8.136 23.724 8.208 ;
     RECT  22.489 8.208 23.676 8.232 ;
     RECT  22.489 8.232 23.724 8.304 ;
     RECT  22.489 8.304 23.676 8.328 ;
    LAYER M5 ;
     RECT  3.816 0.016 3.888 0.084 ;
     RECT  3.912 0.016 3.984 0.084 ;
     RECT  4.008 0.016 4.08 0.084 ;
     RECT  4.104 0.016 4.176 0.084 ;
     RECT  4.2 0.016 4.272 0.084 ;
     RECT  4.296 0.016 4.368 0.084 ;
     RECT  4.392 0.016 4.464 0.084 ;
     RECT  4.488 0.016 4.56 0.084 ;
     RECT  4.584 0.016 4.656 0.084 ;
     RECT  4.68 0.016 4.752 0.084 ;
     RECT  4.776 0.016 4.848 0.084 ;
     RECT  4.872 0.016 4.944 0.084 ;
     RECT  4.968 0.016 5.04 0.084 ;
     RECT  5.064 0.016 5.136 0.084 ;
     RECT  5.16 0.016 5.232 0.084 ;
     RECT  5.256 0.016 5.328 0.084 ;
     RECT  5.352 0.016 5.424 0.084 ;
     RECT  5.448 0.016 5.52 0.084 ;
     RECT  5.544 0.016 5.616 0.084 ;
     RECT  5.64 0.016 5.712 0.084 ;
     RECT  5.736 0.016 5.808 0.084 ;
     RECT  5.832 0.016 5.904 0.084 ;
     RECT  5.928 0.016 6 0.084 ;
     RECT  6.024 0.016 6.096 0.084 ;
     RECT  6.12 0.016 6.192 0.084 ;
     RECT  6.216 0.016 6.288 0.084 ;
     RECT  6.312 0.016 6.384 0.084 ;
     RECT  6.408 0.016 6.48 0.084 ;
     RECT  6.504 0.016 6.576 0.084 ;
     RECT  6.6 0.016 6.672 0.084 ;
     RECT  6.696 0.016 6.768 0.084 ;
     RECT  6.792 0.016 6.864 0.084 ;
     RECT  6.888 0.016 6.96 0.084 ;
     RECT  6.984 0.016 7.056 0.084 ;
     RECT  7.08 0.016 7.152 0.084 ;
     RECT  7.176 0.016 7.248 0.084 ;
     RECT  7.272 0.016 7.344 0.084 ;
     RECT  7.368 0.016 7.44 0.084 ;
     RECT  7.464 0.016 7.536 0.084 ;
     RECT  7.56 0.016 7.632 0.084 ;
     RECT  7.656 0.016 7.728 0.084 ;
     RECT  7.752 0.016 7.824 0.084 ;
     RECT  7.848 0.016 7.92 0.084 ;
     RECT  7.944 0.016 8.016 0.084 ;
     RECT  8.04 0.016 8.112 0.084 ;
     RECT  8.136 0.016 8.208 0.084 ;
     RECT  8.232 0.016 8.304 0.084 ;
     RECT  8.328 0.016 8.4 0.084 ;
     RECT  8.424 0.016 8.496 0.084 ;
     RECT  8.52 0.016 8.592 0.084 ;
     RECT  8.616 0.016 8.688 0.084 ;
     RECT  8.712 0.016 8.784 0.084 ;
     RECT  8.808 0.016 8.88 0.084 ;
     RECT  8.904 0.016 8.976 0.084 ;
     RECT  9 0.016 9.072 0.084 ;
     RECT  9.096 0.016 9.168 0.084 ;
     RECT  9.192 0.016 9.264 0.084 ;
     RECT  9.288 0.016 9.36 0.084 ;
     RECT  9.384 0.016 9.456 0.084 ;
     RECT  9.48 0.016 9.552 0.084 ;
     RECT  9.576 0.016 9.648 0.084 ;
     RECT  9.672 0.016 9.744 0.084 ;
     RECT  9.768 0.016 9.84 0.084 ;
     RECT  9.864 0.016 9.936 0.084 ;
     RECT  9.96 0.016 10.032 0.084 ;
     RECT  10.056 0.016 10.128 0.084 ;
     RECT  10.152 0.016 10.224 0.084 ;
     RECT  10.248 0.016 10.32 0.084 ;
     RECT  3.792 0.084 10.344 0.277 ;
     RECT  3.792 0.277 10.488 0.515 ;
     RECT  12.384 0.181 12.408 0.565 ;
     RECT  11.568 0.565 12.408 0.949 ;
     RECT  3.792 0.515 10.344 0.995 ;
     RECT  8.208 0.995 10.344 1.139 ;
     RECT  8.592 1.139 10.344 1.621 ;
     RECT  11.424 0.949 12.408 1.621 ;
     RECT  8.592 1.621 12.408 1.765 ;
     RECT  8.592 1.765 12.888 1.957 ;
     RECT  8.592 1.957 13.608 2.003 ;
     RECT  3.792 0.995 7.176 2.137 ;
     RECT  8.592 2.003 9.864 2.137 ;
     RECT  2.4 2.137 2.52 2.151 ;
     RECT  18.6 2.137 18.72 2.151 ;
     RECT  2.4 2.151 2.712 2.821 ;
     RECT  3.792 2.137 9.864 2.821 ;
     RECT  2.4 2.821 9.864 2.915 ;
     RECT  10.992 2.003 13.608 3.059 ;
     RECT  11.04 3.059 13.608 3.635 ;
     RECT  11.04 3.635 11.736 3.683 ;
     RECT  12.72 3.635 13.608 4.067 ;
     RECT  13.104 4.067 13.608 4.357 ;
     RECT  7.392 2.915 9.864 4.405 ;
     RECT  11.04 3.683 11.688 4.405 ;
     RECT  0.144 3.013 0.168 4.451 ;
     RECT  2.4 2.915 6.408 4.501 ;
     RECT  7.392 4.405 11.688 4.501 ;
     RECT  2.4 4.501 11.688 4.739 ;
     RECT  18.6 2.151 18.912 5.077 ;
     RECT  13.104 4.357 13.704 5.459 ;
     RECT  7.8 4.739 11.688 5.653 ;
     RECT  13.104 5.459 13.512 5.653 ;
     RECT  15.264 5.413 15.288 5.747 ;
     RECT  7.8 5.653 13.512 6.565 ;
     RECT  2.4 4.739 6.648 7.333 ;
     RECT  7.68 6.565 13.512 7.381 ;
     RECT  15.648 6.229 15.672 7.381 ;
     RECT  14.784 7.381 15.672 7.859 ;
     RECT  7.632 7.381 13.512 7.907 ;
     RECT  18.048 5.077 18.912 8.051 ;
     RECT  7.632 7.907 8.328 8.243 ;
     RECT  14.784 7.859 14.808 8.243 ;
     RECT  2.304 7.333 6.648 8.483 ;
     RECT  9.696 7.907 13.512 8.579 ;
     RECT  7.632 8.243 8.232 8.771 ;
     RECT  9.792 8.579 13.512 9.155 ;
     RECT  18.6 8.051 18.912 9.253 ;
     RECT  10.944 9.155 12.024 9.923 ;
     RECT  0.144 8.821 0.168 10.019 ;
     RECT  2.4 8.483 6.648 10.117 ;
     RECT  7.68 8.771 8.232 10.117 ;
     RECT  2.4 10.117 8.232 10.213 ;
     RECT  2.304 10.213 8.232 10.355 ;
     RECT  13.2 9.155 13.512 10.357 ;
     RECT  2.4 10.355 8.232 10.403 ;
     RECT  7.8 10.403 8.232 10.741 ;
     RECT  13.2 10.357 13.656 10.741 ;
     RECT  18.336 9.253 18.912 10.835 ;
     RECT  2.4 10.403 6.744 11.171 ;
     RECT  10.944 9.923 11.112 11.221 ;
     RECT  10.944 11.221 11.976 11.459 ;
     RECT  7.8 10.741 8.28 11.699 ;
     RECT  11.088 11.459 11.976 11.747 ;
     RECT  18.6 10.835 18.912 11.941 ;
     RECT  11.232 11.747 11.976 12.035 ;
     RECT  7.8 11.699 8.232 12.563 ;
     RECT  13.2 10.741 14.232 13.045 ;
     RECT  2.4 11.171 6.648 13.139 ;
     RECT  17.088 12.517 17.112 13.139 ;
     RECT  4.704 13.139 6.648 13.235 ;
     RECT  13.2 13.045 14.856 13.523 ;
     RECT  18.336 11.941 18.912 13.573 ;
     RECT  13.2 13.523 13.512 13.621 ;
     RECT  6.624 13.235 6.648 13.669 ;
     RECT  7.8 12.563 8.112 13.669 ;
     RECT  4.704 13.235 5.448 13.715 ;
     RECT  6.624 13.669 8.112 13.811 ;
     RECT  2.4 13.139 3.672 14.291 ;
     RECT  14.832 13.523 14.856 14.339 ;
     RECT  4.704 13.715 4.728 14.867 ;
     RECT  7.008 13.811 8.112 15.443 ;
     RECT  12.528 13.621 13.512 15.589 ;
     RECT  17.616 13.573 18.912 15.781 ;
     RECT  11.232 12.035 11.256 15.829 ;
     RECT  10.848 15.829 11.256 15.875 ;
     RECT  12.528 15.589 14.088 15.875 ;
     RECT  12.912 15.875 14.088 15.923 ;
     RECT  17.616 15.781 19.032 15.973 ;
     RECT  9.744 15.925 9.768 16.453 ;
     RECT  10.848 15.875 10.872 16.453 ;
     RECT  9.744 16.453 10.872 16.499 ;
     RECT  17.52 15.973 19.032 16.883 ;
     RECT  12.912 15.923 13.608 17.075 ;
     RECT  13.008 17.075 13.608 17.077 ;
     RECT  16.512 16.453 16.536 17.077 ;
     RECT  17.52 16.883 17.544 17.077 ;
     RECT  9.888 16.499 10.872 17.171 ;
     RECT  9.888 17.171 10.104 17.267 ;
     RECT  16.512 17.077 17.544 17.413 ;
     RECT  16.464 17.413 17.544 17.461 ;
     RECT  13.008 17.077 13.944 17.605 ;
     RECT  15.888 17.461 17.544 17.605 ;
     RECT  13.008 17.605 17.544 17.651 ;
     RECT  18.6 16.883 19.032 18.133 ;
     RECT  6.096 16.261 6.12 18.181 ;
     RECT  10.08 17.267 10.104 18.181 ;
     RECT  13.008 17.651 17.064 18.805 ;
     RECT  5.76 18.181 6.12 19.379 ;
     RECT  10.08 18.181 11.016 19.523 ;
     RECT  10.896 19.523 11.016 19.861 ;
     RECT  12.144 18.805 17.064 19.861 ;
     RECT  6.096 19.379 6.12 20.051 ;
     RECT  10.896 19.861 17.064 20.627 ;
     RECT  2.4 14.291 2.712 21.609 ;
     RECT  7.8 15.443 8.112 21.609 ;
     RECT  2.4 21.609 2.52 21.623 ;
     RECT  7.8 21.609 7.92 21.623 ;
     RECT  18.6 18.133 19.848 21.623 ;
     RECT  18.768 21.623 19.848 21.637 ;
     RECT  10.896 20.627 17.016 22.789 ;
     RECT  10.8 22.789 17.016 23.651 ;
     RECT  10.8 23.651 16.872 23.676 ;
     RECT  10.824 23.676 10.896 23.696 ;
     RECT  10.92 23.676 10.992 23.696 ;
     RECT  11.016 23.676 11.088 23.696 ;
     RECT  11.112 23.676 11.184 23.696 ;
     RECT  11.208 23.676 11.28 23.696 ;
     RECT  11.304 23.676 11.376 23.696 ;
     RECT  11.4 23.676 11.472 23.696 ;
     RECT  11.496 23.676 11.568 23.696 ;
     RECT  11.592 23.676 11.664 23.696 ;
     RECT  11.688 23.676 11.76 23.696 ;
     RECT  11.784 23.676 11.856 23.696 ;
     RECT  11.88 23.676 11.952 23.696 ;
     RECT  11.976 23.676 12.048 23.696 ;
     RECT  12.072 23.676 12.144 23.696 ;
     RECT  12.168 23.676 12.24 23.696 ;
     RECT  12.264 23.676 12.336 23.696 ;
     RECT  12.36 23.676 12.432 23.696 ;
     RECT  12.456 23.676 12.528 23.696 ;
     RECT  12.552 23.676 12.624 23.696 ;
     RECT  12.648 23.676 12.72 23.696 ;
     RECT  12.744 23.676 12.816 23.696 ;
     RECT  12.84 23.676 12.912 23.696 ;
     RECT  12.936 23.676 13.008 23.696 ;
     RECT  13.032 23.676 13.104 23.696 ;
     RECT  13.128 23.676 13.2 23.696 ;
     RECT  13.224 23.676 13.296 23.696 ;
     RECT  13.32 23.676 13.392 23.696 ;
     RECT  13.416 23.676 13.488 23.696 ;
     RECT  13.512 23.676 13.584 23.696 ;
     RECT  13.608 23.676 13.68 23.696 ;
     RECT  13.704 23.676 13.776 23.696 ;
     RECT  13.8 23.676 13.872 23.696 ;
     RECT  13.896 23.676 13.968 23.696 ;
     RECT  13.992 23.676 14.064 23.696 ;
     RECT  14.088 23.676 14.16 23.696 ;
     RECT  14.184 23.676 14.256 23.696 ;
     RECT  14.28 23.676 14.352 23.696 ;
     RECT  14.376 23.676 14.448 23.696 ;
     RECT  14.472 23.676 14.544 23.696 ;
     RECT  14.568 23.676 14.64 23.696 ;
     RECT  14.664 23.676 14.736 23.696 ;
     RECT  14.76 23.676 14.832 23.696 ;
     RECT  14.856 23.676 14.928 23.696 ;
     RECT  14.952 23.676 15.024 23.696 ;
     RECT  15.048 23.676 15.12 23.696 ;
     RECT  15.144 23.676 15.216 23.696 ;
     RECT  15.24 23.676 15.312 23.696 ;
     RECT  15.336 23.676 15.408 23.696 ;
     RECT  15.432 23.676 15.504 23.696 ;
     RECT  15.528 23.676 15.6 23.696 ;
     RECT  15.624 23.676 15.696 23.696 ;
     RECT  15.72 23.676 15.792 23.696 ;
     RECT  15.816 23.676 15.888 23.696 ;
     RECT  15.912 23.676 15.984 23.696 ;
     RECT  16.008 23.676 16.08 23.696 ;
     RECT  16.104 23.676 16.176 23.696 ;
     RECT  16.2 23.676 16.272 23.696 ;
     RECT  16.296 23.676 16.368 23.696 ;
     RECT  16.392 23.676 16.464 23.696 ;
     RECT  16.488 23.676 16.56 23.696 ;
     RECT  16.584 23.676 16.656 23.696 ;
     RECT  16.68 23.676 16.752 23.696 ;
     RECT  16.776 23.676 16.848 23.696 ;
     RECT  18.768 21.637 19.944 23.676 ;
     RECT  18.792 23.676 18.864 23.696 ;
     RECT  18.888 23.676 18.96 23.696 ;
     RECT  18.984 23.676 19.056 23.696 ;
     RECT  19.08 23.676 19.152 23.696 ;
     RECT  19.176 23.676 19.248 23.696 ;
     RECT  19.272 23.676 19.344 23.696 ;
     RECT  19.368 23.676 19.44 23.696 ;
     RECT  19.464 23.676 19.536 23.696 ;
     RECT  19.56 23.676 19.632 23.696 ;
     RECT  19.656 23.676 19.728 23.696 ;
     RECT  19.752 23.676 19.824 23.696 ;
     RECT  19.848 23.676 19.92 23.696 ;
     RECT  10.344 0.515 10.488 0.565 ;
     RECT  10.344 0.565 11.568 0.949 ;
     RECT  10.344 0.949 11.424 1.621 ;
     RECT  7.176 0.995 8.208 1.139 ;
     RECT  7.176 1.139 8.592 2.137 ;
     RECT  9.864 2.003 10.992 3.059 ;
     RECT  2.52 2.137 3.792 2.151 ;
     RECT  2.712 2.151 3.792 2.821 ;
     RECT  6.408 2.915 7.392 4.501 ;
     RECT  9.864 3.059 11.04 4.405 ;
     RECT  11.736 3.635 12.72 3.683 ;
     RECT  11.688 3.683 12.72 4.067 ;
     RECT  11.688 4.067 13.104 5.653 ;
     RECT  6.648 4.739 7.8 6.565 ;
     RECT  6.648 6.565 7.68 7.381 ;
     RECT  6.648 7.381 7.632 8.771 ;
     RECT  13.512 7.381 14.784 8.243 ;
     RECT  8.328 7.907 9.696 8.243 ;
     RECT  18.336 8.051 18.6 9.253 ;
     RECT  8.232 8.243 9.696 8.579 ;
     RECT  6.648 8.771 7.68 10.117 ;
     RECT  12.024 9.155 13.2 9.923 ;
     RECT  11.112 9.923 13.2 11.221 ;
     RECT  6.744 10.403 7.8 11.171 ;
     RECT  18.336 10.835 18.6 11.941 ;
     RECT  6.648 11.171 7.8 13.669 ;
     RECT  11.976 11.221 13.2 12.035 ;
     RECT  17.112 12.517 18.336 13.139 ;
     RECT  3.672 13.139 4.704 14.291 ;
     RECT  17.616 13.139 18.336 13.573 ;
     RECT  5.448 13.235 6.624 13.715 ;
     RECT  13.512 13.523 14.832 14.339 ;
     RECT  11.256 13.621 12.528 15.875 ;
     RECT  13.512 14.339 14.088 15.589 ;
     RECT  13.608 15.923 13.944 17.077 ;
     RECT  9.768 15.925 10.848 16.453 ;
     RECT  16.536 16.453 17.52 17.077 ;
     RECT  17.544 16.883 18.6 17.651 ;
     RECT  10.104 17.171 10.872 18.181 ;
     RECT  11.016 18.805 12.144 19.861 ;
  END
END ot_hbm_status_join_fa
END LIBRARY
